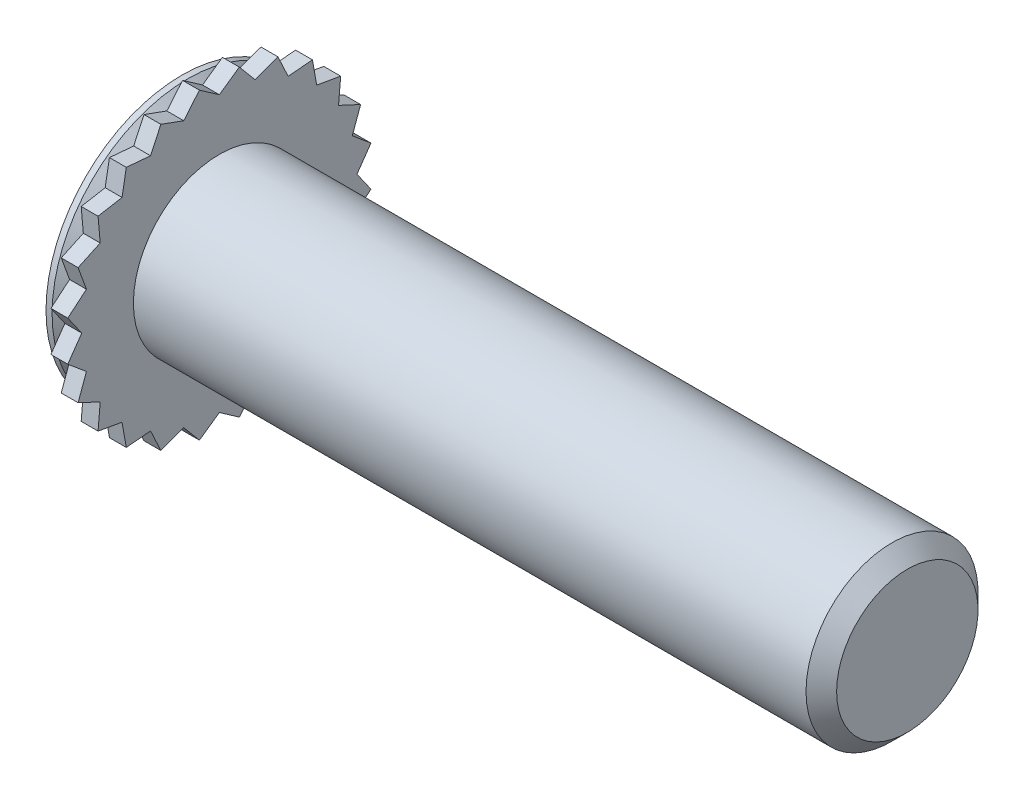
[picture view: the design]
ISO-10303-21;
HEADER;
FILE_DESCRIPTION(('STEP AP214'),'2;1');
FILE_NAME('part.step','',(''),(''),'','','');
FILE_SCHEMA(('AUTOMOTIVE_DESIGN { 1 0 10303 214 1 1 1 1 }'));
ENDSEC;
DATA;
#1=APPLICATION_CONTEXT('core data for automotive mechanical design processes');
#2=APPLICATION_PROTOCOL_DEFINITION('international standard','automotive_design',2000,#1);
#3=PRODUCT_CONTEXT('',#1,'mechanical');
#4=PRODUCT('Part','Part','',(#3));
#5=PRODUCT_RELATED_PRODUCT_CATEGORY('part','',(#4));
#6=PRODUCT_DEFINITION_FORMATION('','',#4);
#7=PRODUCT_DEFINITION_CONTEXT('part definition',#1,'design');
#8=PRODUCT_DEFINITION('design','',#6,#7);
#9=PRODUCT_DEFINITION_SHAPE('','',#8);
#10=(LENGTH_UNIT() NAMED_UNIT(*) SI_UNIT(.MILLI.,.METRE.));
#11=(NAMED_UNIT(*) PLANE_ANGLE_UNIT() SI_UNIT($,.RADIAN.));
#12=(NAMED_UNIT(*) SI_UNIT($,.STERADIAN.) SOLID_ANGLE_UNIT());
#13=UNCERTAINTY_MEASURE_WITH_UNIT(LENGTH_MEASURE(1.E-05),#10,'distance_accuracy_value','');
#14=(GEOMETRIC_REPRESENTATION_CONTEXT(3) GLOBAL_UNCERTAINTY_ASSIGNED_CONTEXT((#13)) GLOBAL_UNIT_ASSIGNED_CONTEXT((#10,
#11,#12)) REPRESENTATION_CONTEXT('',''));
#15=CARTESIAN_POINT('',(0.,0.,0.));
#16=DIRECTION('',(0.,0.,1.));
#17=DIRECTION('',(1.,0.,0.));
#18=AXIS2_PLACEMENT_3D('',#15,#16,#17);
#19=CARTESIAN_POINT('',(1.09,4.445,0.));
#20=DIRECTION('',(1.,0.,0.));
#21=DIRECTION('',(0.,0.,-1.));
#22=AXIS2_PLACEMENT_3D('',#19,#20,#21);
#23=PLANE('',#22);
#24=DIRECTION('',(0.,0.93960568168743,0.34225891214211));
#25=VECTOR('',#24,1.);
#26=CARTESIAN_POINT('',(1.09,1.70102785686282,4.10664452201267));
#27=LINE('',#26,#25);
#28=CARTESIAN_POINT('',(1.09,1.03540558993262,3.86418626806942));
#29=VERTEX_POINT('',#28);
#30=CARTESIAN_POINT('',(1.09,1.70102785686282,4.10664452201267));
#31=VERTEX_POINT('',#30);
#32=EDGE_CURVE('E593',#29,#31,#27,.T.);
#33=ORIENTED_EDGE('',*,*,#32,.F.);
#34=DIRECTION('',(0.,0.642592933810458,-0.766207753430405));
#35=VECTOR('',#34,1.);
#36=CARTESIAN_POINT('',(1.09,1.03540558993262,3.86418626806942));
#37=LINE('',#36,#35);
#38=CARTESIAN_POINT('',(1.09,0.580188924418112,4.40697240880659));
#39=VERTEX_POINT('',#38);
#40=EDGE_CURVE('E597',#39,#29,#37,.T.);
#41=ORIENTED_EDGE('',*,*,#40,.F.);
#42=DIRECTION('',(0.,0.819006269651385,0.57378456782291));
#43=VECTOR('',#42,1.);
#44=CARTESIAN_POINT('',(1.09,0.580188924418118,4.40697240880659));
#45=LINE('',#44,#43);
#46=CARTESIAN_POINT('',(1.09,0.,4.0005));
#47=VERTEX_POINT('',#46);
#48=EDGE_CURVE('E365',#47,#39,#45,.T.);
#49=ORIENTED_EDGE('',*,*,#48,.F.);
#50=DIRECTION('',(0.,0.819006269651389,-0.573784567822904));
#51=VECTOR('',#50,1.);
#52=CARTESIAN_POINT('',(1.09,0.,4.0005));
#53=LINE('',#52,#51);
#54=CARTESIAN_POINT('',(1.09,-0.580188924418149,4.40697240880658));
#55=VERTEX_POINT('',#54);
#56=EDGE_CURVE('E648',#55,#47,#53,.T.);
#57=ORIENTED_EDGE('',*,*,#56,.F.);
#58=DIRECTION('',(0.,0.642592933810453,0.76620775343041));
#59=VECTOR('',#58,1.);
#60=CARTESIAN_POINT('',(1.09,-0.580188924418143,4.40697240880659));
#61=LINE('',#60,#59);
#62=CARTESIAN_POINT('',(1.09,-1.03540558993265,3.86418626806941));
#63=VERTEX_POINT('',#62);
#64=EDGE_CURVE('E347',#63,#55,#61,.T.);
#65=ORIENTED_EDGE('',*,*,#64,.F.);
#66=DIRECTION('',(0.,0.939605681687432,-0.342258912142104));
#67=VECTOR('',#66,1.);
#68=CARTESIAN_POINT('',(1.09,-1.03540558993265,3.86418626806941));
#69=LINE('',#68,#67);
#70=CARTESIAN_POINT('',(1.09,-1.70102785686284,4.10664452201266));
#71=VERTEX_POINT('',#70);
#72=EDGE_CURVE('E662',#71,#63,#69,.T.);
#73=ORIENTED_EDGE('',*,*,#72,.F.);
#74=DIRECTION('',(0.,0.422387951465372,0.906415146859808));
#75=VECTOR('',#74,1.);
#76=CARTESIAN_POINT('',(1.09,-1.70102785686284,4.10664452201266));
#77=LINE('',#76,#75);
#78=CARTESIAN_POINT('',(1.09,-2.00025000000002,3.46453462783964));
#79=VERTEX_POINT('',#78);
#80=EDGE_CURVE('E352',#79,#71,#77,.T.);
#81=ORIENTED_EDGE('',*,*,#80,.F.);
#82=DIRECTION('',(0.,0.996172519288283,-0.0874088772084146));
#83=VECTOR('',#82,1.);
#84=CARTESIAN_POINT('',(1.09,-2.00025000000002,3.46453462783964));
#85=LINE('',#84,#83);
#86=CARTESIAN_POINT('',(1.09,-2.70594455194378,3.52645559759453));
#87=VERTEX_POINT('',#86);
#88=EDGE_CURVE('E368',#87,#79,#85,.T.);
#89=ORIENTED_EDGE('',*,*,#88,.F.);
#90=DIRECTION('',(0.,0.173397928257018,0.984851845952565));
#91=VECTOR('',#90,1.);
#92=CARTESIAN_POINT('',(1.09,-2.70594455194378,3.52645559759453));
#93=LINE('',#92,#91);
#94=CARTESIAN_POINT('',(1.09,-2.8287806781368,2.82878067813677));
#95=VERTEX_POINT('',#94);
#96=EDGE_CURVE('E676',#95,#87,#93,.T.);
#97=ORIENTED_EDGE('',*,*,#96,.F.);
#98=DIRECTION('',(0.,0.984851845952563,0.173397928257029));
#99=VECTOR('',#98,1.);
#100=CARTESIAN_POINT('',(1.09,-2.8287806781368,2.82878067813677));
#101=LINE('',#100,#99);
#102=CARTESIAN_POINT('',(1.09,-3.52645559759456,2.70594455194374));
#103=VERTEX_POINT('',#102);
#104=EDGE_CURVE('E678',#103,#95,#101,.T.);
#105=ORIENTED_EDGE('',*,*,#104,.F.);
#106=DIRECTION('',(0.,-0.087408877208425,0.996172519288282));
#107=VECTOR('',#106,1.);
#108=CARTESIAN_POINT('',(1.09,-3.52645559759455,2.70594455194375));
#109=LINE('',#108,#107);
#110=CARTESIAN_POINT('',(1.09,-3.46453462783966,2.00024999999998));
#111=VERTEX_POINT('',#110);
#112=EDGE_CURVE('E379',#111,#103,#109,.T.);
#113=ORIENTED_EDGE('',*,*,#112,.F.);
#114=DIRECTION('',(0.,0.906415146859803,0.422387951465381));
#115=VECTOR('',#114,1.);
#116=CARTESIAN_POINT('',(1.09,-3.46453462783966,2.00024999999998));
#117=LINE('',#116,#115);
#118=CARTESIAN_POINT('',(1.09,-4.10664452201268,1.7010278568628));
#119=VERTEX_POINT('',#118);
#120=EDGE_CURVE('E377',#119,#111,#117,.T.);
#121=ORIENTED_EDGE('',*,*,#120,.F.);
#122=DIRECTION('',(0.,-0.342258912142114,0.939605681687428));
#123=VECTOR('',#122,1.);
#124=CARTESIAN_POINT('',(1.09,-4.10664452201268,1.7010278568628));
#125=LINE('',#124,#123);
#126=CARTESIAN_POINT('',(1.09,-3.86418626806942,1.03540558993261));
#127=VERTEX_POINT('',#126);
#128=EDGE_CURVE('E688',#127,#119,#125,.T.);
#129=ORIENTED_EDGE('',*,*,#128,.F.);
#130=DIRECTION('',(0.,0.766207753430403,0.642592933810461));
#131=VECTOR('',#130,1.);
#132=CARTESIAN_POINT('',(1.09,-3.86418626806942,1.03540558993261));
#133=LINE('',#132,#131);
#134=CARTESIAN_POINT('',(1.09,-4.40697240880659,0.580188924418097));
#135=VERTEX_POINT('',#134);
#136=EDGE_CURVE('E692',#135,#127,#133,.T.);
#137=ORIENTED_EDGE('',*,*,#136,.F.);
#138=DIRECTION('',(0.,-0.573784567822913,0.819006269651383));
#139=VECTOR('',#138,1.);
#140=CARTESIAN_POINT('',(1.09,-4.40697240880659,0.580188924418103));
#141=LINE('',#140,#139);
#142=CARTESIAN_POINT('',(1.09,-4.0005,0.));
#143=VERTEX_POINT('',#142);
#144=EDGE_CURVE('E396',#143,#135,#141,.T.);
#145=ORIENTED_EDGE('',*,*,#144,.F.);
#146=DIRECTION('',(0.,0.573784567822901,0.819006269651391));
#147=VECTOR('',#146,1.);
#148=CARTESIAN_POINT('',(1.09,-4.0005,0.));
#149=LINE('',#148,#147);
#150=CARTESIAN_POINT('',(1.09,-4.40697240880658,-0.580188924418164));
#151=VERTEX_POINT('',#150);
#152=EDGE_CURVE('E394',#151,#143,#149,.T.);
#153=ORIENTED_EDGE('',*,*,#152,.F.);
#154=DIRECTION('',(0.,-0.766207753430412,0.64259293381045));
#155=VECTOR('',#154,1.);
#156=CARTESIAN_POINT('',(1.09,-4.40697240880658,-0.580188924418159));
#157=LINE('',#156,#155);
#158=CARTESIAN_POINT('',(1.09,-3.86418626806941,-1.03540558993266));
#159=VERTEX_POINT('',#158);
#160=EDGE_CURVE('E703',#159,#151,#157,.T.);
#161=ORIENTED_EDGE('',*,*,#160,.F.);
#162=DIRECTION('',(0.,0.342258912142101,0.939605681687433));
#163=VECTOR('',#162,1.);
#164=CARTESIAN_POINT('',(1.09,-3.86418626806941,-1.03540558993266));
#165=LINE('',#164,#163);
#166=CARTESIAN_POINT('',(1.09,-4.10664452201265,-1.70102785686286));
#167=VERTEX_POINT('',#166);
#168=EDGE_CURVE('E707',#167,#159,#165,.T.);
#169=ORIENTED_EDGE('',*,*,#168,.F.);
#170=DIRECTION('',(0.,-0.906415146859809,0.422387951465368));
#171=VECTOR('',#170,1.);
#172=CARTESIAN_POINT('',(1.09,-4.10664452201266,-1.70102785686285));
#173=LINE('',#172,#171);
#174=CARTESIAN_POINT('',(1.09,-3.46453462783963,-2.00025000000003));
#175=VERTEX_POINT('',#174);
#176=EDGE_CURVE('E413',#175,#167,#173,.T.);
#177=ORIENTED_EDGE('',*,*,#176,.F.);
#178=DIRECTION('',(0.,0.087408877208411,0.996172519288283));
#179=VECTOR('',#178,1.);
#180=CARTESIAN_POINT('',(1.09,-3.46453462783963,-2.00025000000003));
#181=LINE('',#180,#179);
#182=CARTESIAN_POINT('',(1.09,-3.52645559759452,-2.70594455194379));
#183=VERTEX_POINT('',#182);
#184=EDGE_CURVE('E411',#183,#175,#181,.T.);
#185=ORIENTED_EDGE('',*,*,#184,.F.);
#186=DIRECTION('',(0.,-0.984851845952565,0.173397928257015));
#187=VECTOR('',#186,1.);
#188=CARTESIAN_POINT('',(1.09,-3.52645559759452,-2.70594455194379));
#189=LINE('',#188,#187);
#190=CARTESIAN_POINT('',(1.09,-2.82878067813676,-2.82878067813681));
#191=VERTEX_POINT('',#190);
#192=EDGE_CURVE('E718',#191,#183,#189,.T.);
#193=ORIENTED_EDGE('',*,*,#192,.F.);
#194=DIRECTION('',(0.,-0.173397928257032,0.984851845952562));
#195=VECTOR('',#194,1.);
#196=CARTESIAN_POINT('',(1.09,-2.82878067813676,-2.82878067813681));
#197=LINE('',#196,#195);
#198=CARTESIAN_POINT('',(1.09,-2.70594455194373,-3.52645559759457));
#199=VERTEX_POINT('',#198);
#200=EDGE_CURVE('E722',#199,#191,#197,.T.);
#201=ORIENTED_EDGE('',*,*,#200,.F.);
#202=DIRECTION('',(0.,-0.996172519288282,-0.0874088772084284));
#203=VECTOR('',#202,1.);
#204=CARTESIAN_POINT('',(1.09,-2.70594455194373,-3.52645559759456));
#205=LINE('',#204,#203);
#206=CARTESIAN_POINT('',(1.09,-2.00024999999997,-3.46453462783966));
#207=VERTEX_POINT('',#206);
#208=EDGE_CURVE('E430',#207,#199,#205,.T.);
#209=ORIENTED_EDGE('',*,*,#208,.F.);
#210=DIRECTION('',(0.,-0.422387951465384,0.906415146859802));
#211=VECTOR('',#210,1.);
#212=CARTESIAN_POINT('',(1.09,-2.00024999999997,-3.46453462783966));
#213=LINE('',#212,#211);
#214=CARTESIAN_POINT('',(1.09,-1.70102785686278,-4.10664452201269));
#215=VERTEX_POINT('',#214);
#216=EDGE_CURVE('E428',#215,#207,#213,.T.);
#217=ORIENTED_EDGE('',*,*,#216,.F.);
#218=DIRECTION('',(0.,-0.939605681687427,-0.342258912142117));
#219=VECTOR('',#218,1.);
#220=CARTESIAN_POINT('',(1.09,-1.70102785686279,-4.10664452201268));
#221=LINE('',#220,#219);
#222=CARTESIAN_POINT('',(1.09,-1.0354055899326,-3.86418626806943));
#223=VERTEX_POINT('',#222);
#224=EDGE_CURVE('E733',#223,#215,#221,.T.);
#225=ORIENTED_EDGE('',*,*,#224,.F.);
#226=DIRECTION('',(0.,-0.642592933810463,0.7662077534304));
#227=VECTOR('',#226,1.);
#228=CARTESIAN_POINT('',(1.09,-1.0354055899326,-3.86418626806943));
#229=LINE('',#228,#227);
#230=CARTESIAN_POINT('',(1.09,-0.580188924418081,-4.40697240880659));
#231=VERTEX_POINT('',#230);
#232=EDGE_CURVE('E737',#231,#223,#229,.T.);
#233=ORIENTED_EDGE('',*,*,#232,.F.);
#234=DIRECTION('',(0.,-0.819006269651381,-0.573784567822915));
#235=VECTOR('',#234,1.);
#236=CARTESIAN_POINT('',(1.09,-0.580188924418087,-4.40697240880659));
#237=LINE('',#236,#235);
#238=CARTESIAN_POINT('',(1.09,0.,-4.0005));
#239=VERTEX_POINT('',#238);
#240=EDGE_CURVE('E447',#239,#231,#237,.T.);
#241=ORIENTED_EDGE('',*,*,#240,.F.);
#242=DIRECTION('',(0.,-0.819006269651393,0.573784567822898));
#243=VECTOR('',#242,1.);
#244=CARTESIAN_POINT('',(1.09,0.,-4.0005));
#245=LINE('',#244,#243);
#246=CARTESIAN_POINT('',(1.09,0.58018892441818,-4.40697240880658));
#247=VERTEX_POINT('',#246);
#248=EDGE_CURVE('E445',#247,#239,#245,.T.);
#249=ORIENTED_EDGE('',*,*,#248,.F.);
#250=DIRECTION('',(0.,-0.642592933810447,-0.766207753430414));
#251=VECTOR('',#250,1.);
#252=CARTESIAN_POINT('',(1.09,0.580188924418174,-4.40697240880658));
#253=LINE('',#252,#251);
#254=CARTESIAN_POINT('',(1.09,1.03540558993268,-3.86418626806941));
#255=VERTEX_POINT('',#254);
#256=EDGE_CURVE('E748',#255,#247,#253,.T.);
#257=ORIENTED_EDGE('',*,*,#256,.F.);
#258=DIRECTION('',(0.,-0.939605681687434,0.342258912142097));
#259=VECTOR('',#258,1.);
#260=CARTESIAN_POINT('',(1.09,1.03540558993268,-3.86418626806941));
#261=LINE('',#260,#259);
#262=CARTESIAN_POINT('',(1.09,1.70102785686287,-4.10664452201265));
#263=VERTEX_POINT('',#262);
#264=EDGE_CURVE('E752',#263,#255,#261,.T.);
#265=ORIENTED_EDGE('',*,*,#264,.F.);
#266=DIRECTION('',(0.,-0.422387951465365,-0.906415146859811));
#267=VECTOR('',#266,1.);
#268=CARTESIAN_POINT('',(1.09,1.70102785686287,-4.10664452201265));
#269=LINE('',#268,#267);
#270=CARTESIAN_POINT('',(1.09,2.00025000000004,-3.46453462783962));
#271=VERTEX_POINT('',#270);
#272=EDGE_CURVE('E464',#271,#263,#269,.T.);
#273=ORIENTED_EDGE('',*,*,#272,.F.);
#274=DIRECTION('',(0.,-0.996172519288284,0.0874088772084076));
#275=VECTOR('',#274,1.);
#276=CARTESIAN_POINT('',(1.09,2.00025000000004,-3.46453462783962));
#277=LINE('',#276,#275);
#278=CARTESIAN_POINT('',(1.09,2.70594455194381,-3.52645559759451));
#279=VERTEX_POINT('',#278);
#280=EDGE_CURVE('E462',#279,#271,#277,.T.);
#281=ORIENTED_EDGE('',*,*,#280,.F.);
#282=DIRECTION('',(0.,-0.173397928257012,-0.984851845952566));
#283=VECTOR('',#282,1.);
#284=CARTESIAN_POINT('',(1.09,2.7059445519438,-3.52645559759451));
#285=LINE('',#284,#283);
#286=CARTESIAN_POINT('',(1.09,2.82878067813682,-2.82878067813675));
#287=VERTEX_POINT('',#286);
#288=EDGE_CURVE('E763',#287,#279,#285,.T.);
#289=ORIENTED_EDGE('',*,*,#288,.F.);
#290=DIRECTION('',(0.,-0.984851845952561,-0.173397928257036));
#291=VECTOR('',#290,1.);
#292=CARTESIAN_POINT('',(1.09,2.82878067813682,-2.82878067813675));
#293=LINE('',#292,#291);
#294=CARTESIAN_POINT('',(1.09,3.52645559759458,-2.70594455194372));
#295=VERTEX_POINT('',#294);
#296=EDGE_CURVE('E767',#295,#287,#293,.T.);
#297=ORIENTED_EDGE('',*,*,#296,.F.);
#298=DIRECTION('',(0.,0.0874088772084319,-0.996172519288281));
#299=VECTOR('',#298,1.);
#300=CARTESIAN_POINT('',(1.09,3.52645559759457,-2.70594455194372));
#301=LINE('',#300,#299);
#302=CARTESIAN_POINT('',(1.09,3.46453462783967,-2.00024999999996));
#303=VERTEX_POINT('',#302);
#304=EDGE_CURVE('E481',#303,#295,#301,.T.);
#305=ORIENTED_EDGE('',*,*,#304,.F.);
#306=DIRECTION('',(0.,-0.906415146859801,-0.422387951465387));
#307=VECTOR('',#306,1.);
#308=CARTESIAN_POINT('',(1.09,3.46453462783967,-2.00024999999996));
#309=LINE('',#308,#307);
#310=CARTESIAN_POINT('',(1.09,4.10664452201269,-1.70102785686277));
#311=VERTEX_POINT('',#310);
#312=EDGE_CURVE('E479',#311,#303,#309,.T.);
#313=ORIENTED_EDGE('',*,*,#312,.F.);
#314=DIRECTION('',(0.,0.34225891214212,-0.939605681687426));
#315=VECTOR('',#314,1.);
#316=CARTESIAN_POINT('',(1.09,4.10664452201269,-1.70102785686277));
#317=LINE('',#316,#315);
#318=CARTESIAN_POINT('',(1.09,3.86418626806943,-1.03540558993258));
#319=VERTEX_POINT('',#318);
#320=EDGE_CURVE('E778',#319,#311,#317,.T.);
#321=ORIENTED_EDGE('',*,*,#320,.F.);
#322=DIRECTION('',(0.,-0.766207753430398,-0.642592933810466));
#323=VECTOR('',#322,1.);
#324=CARTESIAN_POINT('',(1.09,3.86418626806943,-1.03540558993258));
#325=LINE('',#324,#323);
#326=CARTESIAN_POINT('',(1.09,4.40697240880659,-0.580188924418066));
#327=VERTEX_POINT('',#326);
#328=EDGE_CURVE('E781',#327,#319,#325,.T.);
#329=ORIENTED_EDGE('',*,*,#328,.F.);
#330=DIRECTION('',(0.,0.573784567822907,-0.819006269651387));
#331=VECTOR('',#330,1.);
#332=CARTESIAN_POINT('',(1.09,4.40697240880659,-0.580188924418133));
#333=LINE('',#332,#331);
#334=CARTESIAN_POINT('',(1.09,4.0005,0.));
#335=VERTEX_POINT('',#334);
#336=EDGE_CURVE('E528',#335,#327,#333,.T.);
#337=ORIENTED_EDGE('',*,*,#336,.F.);
#338=DIRECTION('',(0.,-0.573784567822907,-0.819006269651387));
#339=VECTOR('',#338,1.);
#340=CARTESIAN_POINT('',(1.09,4.0005,0.));
#341=LINE('',#340,#339);
#342=CARTESIAN_POINT('',(1.09,4.40697240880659,0.580188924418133));
#343=VERTEX_POINT('',#342);
#344=EDGE_CURVE('E521',#343,#335,#341,.T.);
#345=ORIENTED_EDGE('',*,*,#344,.F.);
#346=DIRECTION('',(0.,0.766207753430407,-0.642592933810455));
#347=VECTOR('',#346,1.);
#348=CARTESIAN_POINT('',(1.09,4.40697240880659,0.580188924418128));
#349=LINE('',#348,#347);
#350=CARTESIAN_POINT('',(1.09,3.86418626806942,1.03540558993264));
#351=VERTEX_POINT('',#350);
#352=EDGE_CURVE('E512',#351,#343,#349,.T.);
#353=ORIENTED_EDGE('',*,*,#352,.F.);
#354=DIRECTION('',(0.,-0.342258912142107,-0.939605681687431));
#355=VECTOR('',#354,1.);
#356=CARTESIAN_POINT('',(1.09,3.86418626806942,1.03540558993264));
#357=LINE('',#356,#355);
#358=CARTESIAN_POINT('',(1.09,4.10664452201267,1.70102785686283));
#359=VERTEX_POINT('',#358);
#360=EDGE_CURVE('E501',#359,#351,#357,.T.);
#361=ORIENTED_EDGE('',*,*,#360,.F.);
#362=DIRECTION('',(0.,0.906415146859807,-0.422387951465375));
#363=VECTOR('',#362,1.);
#364=CARTESIAN_POINT('',(1.09,4.10664452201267,1.70102785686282));
#365=LINE('',#364,#363);
#366=CARTESIAN_POINT('',(1.09,3.46453462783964,2.00025));
#367=VERTEX_POINT('',#366);
#368=EDGE_CURVE('E635',#367,#359,#365,.T.);
#369=ORIENTED_EDGE('',*,*,#368,.F.);
#370=DIRECTION('',(0.,-0.087408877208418,-0.996172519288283));
#371=VECTOR('',#370,1.);
#372=CARTESIAN_POINT('',(1.09,3.46453462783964,2.00025));
#373=LINE('',#372,#371);
#374=CARTESIAN_POINT('',(1.09,3.52645559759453,2.70594455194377));
#375=VERTEX_POINT('',#374);
#376=EDGE_CURVE('E633',#375,#367,#373,.T.);
#377=ORIENTED_EDGE('',*,*,#376,.F.);
#378=DIRECTION('',(0.,0.984851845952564,-0.173397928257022));
#379=VECTOR('',#378,1.);
#380=CARTESIAN_POINT('',(1.09,3.52645559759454,2.70594455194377));
#381=LINE('',#380,#379);
#382=CARTESIAN_POINT('',(1.09,2.82878067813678,2.82878067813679));
#383=VERTEX_POINT('',#382);
#384=EDGE_CURVE('E617',#383,#375,#381,.T.);
#385=ORIENTED_EDGE('',*,*,#384,.F.);
#386=DIRECTION('',(0.,0.173397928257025,-0.984851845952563));
#387=VECTOR('',#386,1.);
#388=CARTESIAN_POINT('',(1.09,2.82878067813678,2.82878067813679));
#389=LINE('',#388,#387);
#390=CARTESIAN_POINT('',(1.09,2.70594455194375,3.52645559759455));
#391=VERTEX_POINT('',#390);
#392=EDGE_CURVE('E610',#391,#383,#389,.T.);
#393=ORIENTED_EDGE('',*,*,#392,.F.);
#394=DIRECTION('',(0.,0.996172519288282,0.0874088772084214));
#395=VECTOR('',#394,1.);
#396=CARTESIAN_POINT('',(1.09,2.70594455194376,3.52645559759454));
#397=LINE('',#396,#395);
#398=CARTESIAN_POINT('',(1.09,2.00024999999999,3.46453462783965));
#399=VERTEX_POINT('',#398);
#400=EDGE_CURVE('E498',#399,#391,#397,.T.);
#401=ORIENTED_EDGE('',*,*,#400,.F.);
#402=DIRECTION('',(0.,0.422387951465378,-0.906415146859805));
#403=VECTOR('',#402,1.);
#404=CARTESIAN_POINT('',(1.09,2.00024999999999,3.46453462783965));
#405=LINE('',#404,#403);
#406=EDGE_CURVE('E496',#31,#399,#405,.T.);
#407=ORIENTED_EDGE('',*,*,#406,.F.);
#408=EDGE_LOOP('',(#33,#41,#49,#57,#65,#73,#81,#89,#97,#105,#113,#121,#129,#137,#145,#153,#161,
#169,#177,#185,#193,#201,#209,#217,#225,#233,#241,#249,#257,#265,#273,#281,#289,#297,#305,#313,
#321,#329,#337,#345,#353,#361,#369,#377,#385,#393,#401,#407));
#409=FACE_BOUND('',#408,.T.);
#410=CARTESIAN_POINT('',(1.09,0.,0.));
#411=DIRECTION('',(-1.,0.,0.));
#412=DIRECTION('',(0.,0.,1.));
#413=AXIS2_PLACEMENT_3D('',#410,#411,#412);
#414=CIRCLE('',#413,2.5);
#415=CARTESIAN_POINT('',(1.09,0.,2.5));
#416=VERTEX_POINT('',#415);
#417=EDGE_CURVE('E11',#416,#416,#414,.T.);
#418=ORIENTED_EDGE('',*,*,#417,.T.);
#419=EDGE_LOOP('',(#418));
#420=FACE_BOUND('',#419,.T.);
#421=ADVANCED_FACE('F32',(#409,#420),#23,.T.);
#422=CARTESIAN_POINT('',(0.,0.,0.));
#423=DIRECTION('',(-1.,0.,0.));
#424=DIRECTION('',(0.,0.,1.));
#425=AXIS2_PLACEMENT_3D('',#422,#423,#424);
#426=CYLINDRICAL_SURFACE('',#425,2.5);
#427=CARTESIAN_POINT('',(20.6449999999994,0.,0.));
#428=DIRECTION('',(-1.,0.,0.));
#429=DIRECTION('',(0.,0.,1.));
#430=AXIS2_PLACEMENT_3D('',#427,#428,#429);
#431=CIRCLE('',#430,2.5);
#432=CARTESIAN_POINT('',(20.6449999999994,0.,2.5));
#433=VERTEX_POINT('',#432);
#434=EDGE_CURVE('E39',#433,#433,#431,.T.);
#435=ORIENTED_EDGE('',*,*,#434,.T.);
#436=EDGE_LOOP('',(#435));
#437=FACE_BOUND('',#436,.T.);
#438=ORIENTED_EDGE('',*,*,#417,.F.);
#439=EDGE_LOOP('',(#438));
#440=FACE_BOUND('',#439,.T.);
#441=ADVANCED_FACE('F565',(#437,#440),#426,.T.);
#442=CARTESIAN_POINT('',(21.09,0.,0.));
#443=DIRECTION('',(-1.,0.,0.));
#444=DIRECTION('',(0.,0.,1.));
#445=AXIS2_PLACEMENT_3D('',#442,#443,#444);
#446=CONICAL_SURFACE('',#445,2.055,0.785398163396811);
#447=ORIENTED_EDGE('',*,*,#434,.F.);
#448=EDGE_LOOP('',(#447));
#449=FACE_BOUND('',#448,.T.);
#450=CARTESIAN_POINT('',(21.09,0.,0.));
#451=DIRECTION('',(-1.,0.,0.));
#452=DIRECTION('',(0.,0.,1.));
#453=AXIS2_PLACEMENT_3D('',#450,#451,#452);
#454=CIRCLE('',#453,2.055);
#455=CARTESIAN_POINT('',(21.09,0.,2.055));
#456=VERTEX_POINT('',#455);
#457=EDGE_CURVE('E560',#456,#456,#454,.T.);
#458=ORIENTED_EDGE('',*,*,#457,.T.);
#459=EDGE_LOOP('',(#458));
#460=FACE_BOUND('',#459,.T.);
#461=ADVANCED_FACE('F568',(#449,#460),#446,.T.);
#462=CARTESIAN_POINT('',(21.09,2.055,0.));
#463=DIRECTION('',(1.,0.,0.));
#464=DIRECTION('',(0.,0.,-1.));
#465=AXIS2_PLACEMENT_3D('',#462,#463,#464);
#466=PLANE('',#465);
#467=ORIENTED_EDGE('',*,*,#457,.F.);
#468=EDGE_LOOP('',(#467));
#469=FACE_BOUND('',#468,.T.);
#470=ADVANCED_FACE('F571',(#469),#466,.T.);
#471=CARTESIAN_POINT('',(0.545,1.6775,0.));
#472=DIRECTION('',(1.,0.,0.));
#473=DIRECTION('',(0.,0.,-1.));
#474=AXIS2_PLACEMENT_3D('',#471,#472,#473);
#475=PLANE('',#474);
#476=CARTESIAN_POINT('',(0.545,0.,0.));
#477=DIRECTION('',(-1.,0.,0.));
#478=DIRECTION('',(0.,0.,1.));
#479=AXIS2_PLACEMENT_3D('',#476,#477,#478);
#480=CIRCLE('',#479,1.6775);
#481=CARTESIAN_POINT('',(0.545,0.,1.6775));
#482=VERTEX_POINT('',#481);
#483=EDGE_CURVE('E557',#482,#482,#480,.T.);
#484=ORIENTED_EDGE('',*,*,#483,.T.);
#485=EDGE_LOOP('',(#484));
#486=FACE_BOUND('',#485,.T.);
#487=ADVANCED_FACE('F576',(#486),#475,.F.);
#488=CARTESIAN_POINT('',(0.,0.,0.));
#489=DIRECTION('',(-1.,0.,0.));
#490=DIRECTION('',(0.,0.,1.));
#491=AXIS2_PLACEMENT_3D('',#488,#489,#490);
#492=CONICAL_SURFACE('',#491,2.2225,0.78539816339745);
#493=ORIENTED_EDGE('',*,*,#483,.F.);
#494=EDGE_LOOP('',(#493));
#495=FACE_BOUND('',#494,.T.);
#496=CARTESIAN_POINT('',(0.,0.,0.));
#497=DIRECTION('',(-1.,0.,0.));
#498=DIRECTION('',(0.,0.,1.));
#499=AXIS2_PLACEMENT_3D('',#496,#497,#498);
#500=CIRCLE('',#499,2.2225);
#501=CARTESIAN_POINT('',(0.,0.,2.2225));
#502=VERTEX_POINT('',#501);
#503=EDGE_CURVE('E554',#502,#502,#500,.T.);
#504=ORIENTED_EDGE('',*,*,#503,.T.);
#505=EDGE_LOOP('',(#504));
#506=FACE_BOUND('',#505,.T.);
#507=ADVANCED_FACE('F581',(#495,#506),#492,.F.);
#508=CARTESIAN_POINT('',(0.,2.2225,0.));
#509=DIRECTION('',(-1.,0.,0.));
#510=DIRECTION('',(0.,0.,1.));
#511=AXIS2_PLACEMENT_3D('',#508,#509,#510);
#512=PLANE('',#511);
#513=CARTESIAN_POINT('',(0.,0.,0.));
#514=DIRECTION('',(-1.,0.,0.));
#515=DIRECTION('',(0.,0.,1.));
#516=AXIS2_PLACEMENT_3D('',#513,#514,#515);
#517=CIRCLE('',#516,3.95);
#518=CARTESIAN_POINT('',(0.,0.,3.95));
#519=VERTEX_POINT('',#518);
#520=EDGE_CURVE('E551',#519,#519,#517,.T.);
#521=ORIENTED_EDGE('',*,*,#520,.T.);
#522=EDGE_LOOP('',(#521));
#523=FACE_BOUND('',#522,.T.);
#524=ORIENTED_EDGE('',*,*,#503,.F.);
#525=EDGE_LOOP('',(#524));
#526=FACE_BOUND('',#525,.T.);
#527=ADVANCED_FACE('F1062',(#523,#526),#512,.T.);
#528=CARTESIAN_POINT('',(0.,0.,0.));
#529=DIRECTION('',(-1.,0.,0.));
#530=DIRECTION('',(0.,0.,1.));
#531=AXIS2_PLACEMENT_3D('',#528,#529,#530);
#532=CYLINDRICAL_SURFACE('',#531,3.95);
#533=ORIENTED_EDGE('',*,*,#520,.F.);
#534=EDGE_LOOP('',(#533));
#535=FACE_BOUND('',#534,.T.);
#536=CARTESIAN_POINT('',(0.1778,0.,0.));
#537=DIRECTION('',(-1.,0.,0.));
#538=DIRECTION('',(0.,0.,1.));
#539=AXIS2_PLACEMENT_3D('',#536,#537,#538);
#540=CIRCLE('',#539,3.95);
#541=CARTESIAN_POINT('',(0.1778,0.,3.95));
#542=VERTEX_POINT('',#541);
#543=EDGE_CURVE('E548',#542,#542,#540,.T.);
#544=ORIENTED_EDGE('',*,*,#543,.T.);
#545=EDGE_LOOP('',(#544));
#546=FACE_BOUND('',#545,.T.);
#547=ADVANCED_FACE('F1058',(#535,#546),#532,.T.);
#548=CARTESIAN_POINT('',(0.4905,0.,0.));
#549=DIRECTION('',(-1.,0.,0.));
#550=DIRECTION('',(0.,0.,1.));
#551=AXIS2_PLACEMENT_3D('',#548,#549,#550);
#552=CONICAL_SURFACE('',#551,3.6373,0.785398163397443);
#553=ORIENTED_EDGE('',*,*,#543,.F.);
#554=EDGE_LOOP('',(#553));
#555=FACE_BOUND('',#554,.T.);
#556=CARTESIAN_POINT('',(0.4905,0.,0.));
#557=DIRECTION('',(-1.,0.,0.));
#558=DIRECTION('',(0.,0.,1.));
#559=AXIS2_PLACEMENT_3D('',#556,#557,#558);
#560=CIRCLE('',#559,3.6373);
#561=CARTESIAN_POINT('',(0.4905,0.,3.6373));
#562=VERTEX_POINT('',#561);
#563=EDGE_CURVE('E545',#562,#562,#560,.T.);
#564=ORIENTED_EDGE('',*,*,#563,.T.);
#565=EDGE_LOOP('',(#564));
#566=FACE_BOUND('',#565,.T.);
#567=ADVANCED_FACE('F1054',(#555,#566),#552,.T.);
#568=CARTESIAN_POINT('',(0.,0.,0.));
#569=DIRECTION('',(-1.,0.,0.));
#570=DIRECTION('',(0.,0.,1.));
#571=AXIS2_PLACEMENT_3D('',#568,#569,#570);
#572=CYLINDRICAL_SURFACE('',#571,3.6373);
#573=ORIENTED_EDGE('',*,*,#563,.F.);
#574=EDGE_LOOP('',(#573));
#575=FACE_BOUND('',#574,.T.);
#576=CARTESIAN_POINT('',(0.5995,0.,0.));
#577=DIRECTION('',(-1.,0.,0.));
#578=DIRECTION('',(0.,0.,1.));
#579=AXIS2_PLACEMENT_3D('',#576,#577,#578);
#580=CIRCLE('',#579,3.6373);
#581=CARTESIAN_POINT('',(0.5995,0.,3.6373));
#582=VERTEX_POINT('',#581);
#583=EDGE_CURVE('E538',#582,#582,#580,.T.);
#584=ORIENTED_EDGE('',*,*,#583,.T.);
#585=EDGE_LOOP('',(#584));
#586=FACE_BOUND('',#585,.T.);
#587=ADVANCED_FACE('F1050',(#575,#586),#572,.T.);
#588=CARTESIAN_POINT('',(0.5995,4.445,0.));
#589=DIRECTION('',(1.,0.,0.));
#590=DIRECTION('',(0.,0.,-1.));
#591=AXIS2_PLACEMENT_3D('',#588,#589,#590);
#592=PLANE('',#591);
#593=ORIENTED_EDGE('',*,*,#583,.F.);
#594=EDGE_LOOP('',(#593));
#595=FACE_BOUND('',#594,.T.);
#596=DIRECTION('',(0.,0.642592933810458,-0.766207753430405));
#597=VECTOR('',#596,1.);
#598=CARTESIAN_POINT('',(0.5995,1.03540558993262,3.86418626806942));
#599=LINE('',#598,#597);
#600=CARTESIAN_POINT('',(0.5995,0.580188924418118,4.40697240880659));
#601=VERTEX_POINT('',#600);
#602=CARTESIAN_POINT('',(0.5995,1.03540558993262,3.86418626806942));
#603=VERTEX_POINT('',#602);
#604=EDGE_CURVE('E601',#601,#603,#599,.T.);
#605=ORIENTED_EDGE('',*,*,#604,.T.);
#606=DIRECTION('',(0.,0.93960568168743,0.34225891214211));
#607=VECTOR('',#606,1.);
#608=CARTESIAN_POINT('',(0.5995,1.70102785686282,4.10664452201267));
#609=LINE('',#608,#607);
#610=CARTESIAN_POINT('',(0.5995,1.70102785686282,4.10664452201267));
#611=VERTEX_POINT('',#610);
#612=EDGE_CURVE('E603',#603,#611,#609,.T.);
#613=ORIENTED_EDGE('',*,*,#612,.T.);
#614=DIRECTION('',(0.,0.422387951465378,-0.906415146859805));
#615=VECTOR('',#614,1.);
#616=CARTESIAN_POINT('',(0.5995,2.00024999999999,3.46453462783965));
#617=LINE('',#616,#615);
#618=CARTESIAN_POINT('',(0.5995,2.00024999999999,3.46453462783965));
#619=VERTEX_POINT('',#618);
#620=EDGE_CURVE('E497',#611,#619,#617,.T.);
#621=ORIENTED_EDGE('',*,*,#620,.T.);
#622=DIRECTION('',(0.,0.996172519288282,0.0874088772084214));
#623=VECTOR('',#622,1.);
#624=CARTESIAN_POINT('',(0.5995,2.70594455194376,3.52645559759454));
#625=LINE('',#624,#623);
#626=CARTESIAN_POINT('',(0.5995,2.70594455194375,3.52645559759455));
#627=VERTEX_POINT('',#626);
#628=EDGE_CURVE('E493',#619,#627,#625,.T.);
#629=ORIENTED_EDGE('',*,*,#628,.T.);
#630=DIRECTION('',(0.,0.173397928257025,-0.984851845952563));
#631=VECTOR('',#630,1.);
#632=CARTESIAN_POINT('',(0.5995,2.82878067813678,2.82878067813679));
#633=LINE('',#632,#631);
#634=CARTESIAN_POINT('',(0.5995,2.82878067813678,2.82878067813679));
#635=VERTEX_POINT('',#634);
#636=EDGE_CURVE('E613',#627,#635,#633,.T.);
#637=ORIENTED_EDGE('',*,*,#636,.T.);
#638=DIRECTION('',(0.,0.984851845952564,-0.173397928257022));
#639=VECTOR('',#638,1.);
#640=CARTESIAN_POINT('',(0.5995,3.52645559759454,2.70594455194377));
#641=LINE('',#640,#639);
#642=CARTESIAN_POINT('',(0.5995,3.52645559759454,2.70594455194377));
#643=VERTEX_POINT('',#642);
#644=EDGE_CURVE('E616',#635,#643,#641,.T.);
#645=ORIENTED_EDGE('',*,*,#644,.T.);
#646=DIRECTION('',(0.,-0.087408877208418,-0.996172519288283));
#647=VECTOR('',#646,1.);
#648=CARTESIAN_POINT('',(0.5995,3.46453462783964,2.00025));
#649=LINE('',#648,#647);
#650=CARTESIAN_POINT('',(0.5995,3.46453462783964,2.00025));
#651=VERTEX_POINT('',#650);
#652=EDGE_CURVE('E634',#643,#651,#649,.T.);
#653=ORIENTED_EDGE('',*,*,#652,.T.);
#654=DIRECTION('',(0.,0.906415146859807,-0.422387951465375));
#655=VECTOR('',#654,1.);
#656=CARTESIAN_POINT('',(0.5995,4.10664452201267,1.70102785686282));
#657=LINE('',#656,#655);
#658=CARTESIAN_POINT('',(0.5995,4.10664452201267,1.70102785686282));
#659=VERTEX_POINT('',#658);
#660=EDGE_CURVE('E630',#651,#659,#657,.T.);
#661=ORIENTED_EDGE('',*,*,#660,.T.);
#662=DIRECTION('',(0.,-0.342258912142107,-0.939605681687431));
#663=VECTOR('',#662,1.);
#664=CARTESIAN_POINT('',(0.5995,3.86418626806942,1.03540558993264));
#665=LINE('',#664,#663);
#666=CARTESIAN_POINT('',(0.5995,3.86418626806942,1.03540558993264));
#667=VERTEX_POINT('',#666);
#668=EDGE_CURVE('E508',#659,#667,#665,.T.);
#669=ORIENTED_EDGE('',*,*,#668,.T.);
#670=DIRECTION('',(0.,0.766207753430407,-0.642592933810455));
#671=VECTOR('',#670,1.);
#672=CARTESIAN_POINT('',(0.5995,4.40697240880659,0.580188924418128));
#673=LINE('',#672,#671);
#674=CARTESIAN_POINT('',(0.5995,4.40697240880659,0.580188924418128));
#675=VERTEX_POINT('',#674);
#676=EDGE_CURVE('E511',#667,#675,#673,.T.);
#677=ORIENTED_EDGE('',*,*,#676,.T.);
#678=DIRECTION('',(0.,-0.573784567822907,-0.819006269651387));
#679=VECTOR('',#678,1.);
#680=CARTESIAN_POINT('',(0.5995,4.0005,0.));
#681=LINE('',#680,#679);
#682=CARTESIAN_POINT('',(0.5995,4.0005,0.));
#683=VERTEX_POINT('',#682);
#684=EDGE_CURVE('E524',#675,#683,#681,.T.);
#685=ORIENTED_EDGE('',*,*,#684,.T.);
#686=DIRECTION('',(0.,0.573784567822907,-0.819006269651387));
#687=VECTOR('',#686,1.);
#688=CARTESIAN_POINT('',(0.5995,4.40697240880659,-0.580188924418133));
#689=LINE('',#688,#687);
#690=CARTESIAN_POINT('',(0.5995,4.40697240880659,-0.580188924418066));
#691=VERTEX_POINT('',#690);
#692=EDGE_CURVE('E527',#683,#691,#689,.T.);
#693=ORIENTED_EDGE('',*,*,#692,.T.);
#694=DIRECTION('',(0.,-0.766207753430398,-0.642592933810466));
#695=VECTOR('',#694,1.);
#696=CARTESIAN_POINT('',(0.5995,3.86418626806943,-1.03540558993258));
#697=LINE('',#696,#695);
#698=CARTESIAN_POINT('',(0.5995,3.86418626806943,-1.03540558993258));
#699=VERTEX_POINT('',#698);
#700=EDGE_CURVE('E774',#691,#699,#697,.T.);
#701=ORIENTED_EDGE('',*,*,#700,.T.);
#702=DIRECTION('',(0.,0.34225891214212,-0.939605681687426));
#703=VECTOR('',#702,1.);
#704=CARTESIAN_POINT('',(0.5995,4.10664452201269,-1.70102785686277));
#705=LINE('',#704,#703);
#706=CARTESIAN_POINT('',(0.5995,4.10664452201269,-1.70102785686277));
#707=VERTEX_POINT('',#706);
#708=EDGE_CURVE('E777',#699,#707,#705,.T.);
#709=ORIENTED_EDGE('',*,*,#708,.T.);
#710=DIRECTION('',(0.,-0.906415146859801,-0.422387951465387));
#711=VECTOR('',#710,1.);
#712=CARTESIAN_POINT('',(0.5995,3.46453462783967,-2.00024999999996));
#713=LINE('',#712,#711);
#714=CARTESIAN_POINT('',(0.5995,3.46453462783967,-2.00024999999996));
#715=VERTEX_POINT('',#714);
#716=EDGE_CURVE('E480',#707,#715,#713,.T.);
#717=ORIENTED_EDGE('',*,*,#716,.T.);
#718=DIRECTION('',(0.,0.0874088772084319,-0.996172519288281));
#719=VECTOR('',#718,1.);
#720=CARTESIAN_POINT('',(0.5995,3.52645559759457,-2.70594455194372));
#721=LINE('',#720,#719);
#722=CARTESIAN_POINT('',(0.5995,3.52645559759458,-2.70594455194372));
#723=VERTEX_POINT('',#722);
#724=EDGE_CURVE('E476',#715,#723,#721,.T.);
#725=ORIENTED_EDGE('',*,*,#724,.T.);
#726=DIRECTION('',(0.,-0.984851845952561,-0.173397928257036));
#727=VECTOR('',#726,1.);
#728=CARTESIAN_POINT('',(0.5995,2.82878067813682,-2.82878067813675));
#729=LINE('',#728,#727);
#730=CARTESIAN_POINT('',(0.5995,2.82878067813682,-2.82878067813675));
#731=VERTEX_POINT('',#730);
#732=EDGE_CURVE('E759',#723,#731,#729,.T.);
#733=ORIENTED_EDGE('',*,*,#732,.T.);
#734=DIRECTION('',(0.,-0.173397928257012,-0.984851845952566));
#735=VECTOR('',#734,1.);
#736=CARTESIAN_POINT('',(0.5995,2.7059445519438,-3.52645559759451));
#737=LINE('',#736,#735);
#738=CARTESIAN_POINT('',(0.5995,2.7059445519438,-3.52645559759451));
#739=VERTEX_POINT('',#738);
#740=EDGE_CURVE('E762',#731,#739,#737,.T.);
#741=ORIENTED_EDGE('',*,*,#740,.T.);
#742=DIRECTION('',(0.,-0.996172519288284,0.0874088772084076));
#743=VECTOR('',#742,1.);
#744=CARTESIAN_POINT('',(0.5995,2.00025000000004,-3.46453462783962));
#745=LINE('',#744,#743);
#746=CARTESIAN_POINT('',(0.5995,2.00025000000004,-3.46453462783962));
#747=VERTEX_POINT('',#746);
#748=EDGE_CURVE('E463',#739,#747,#745,.T.);
#749=ORIENTED_EDGE('',*,*,#748,.T.);
#750=DIRECTION('',(0.,-0.422387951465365,-0.906415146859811));
#751=VECTOR('',#750,1.);
#752=CARTESIAN_POINT('',(0.5995,1.70102785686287,-4.10664452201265));
#753=LINE('',#752,#751);
#754=CARTESIAN_POINT('',(0.5995,1.70102785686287,-4.10664452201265));
#755=VERTEX_POINT('',#754);
#756=EDGE_CURVE('E459',#747,#755,#753,.T.);
#757=ORIENTED_EDGE('',*,*,#756,.T.);
#758=DIRECTION('',(0.,-0.939605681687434,0.342258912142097));
#759=VECTOR('',#758,1.);
#760=CARTESIAN_POINT('',(0.5995,1.03540558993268,-3.86418626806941));
#761=LINE('',#760,#759);
#762=CARTESIAN_POINT('',(0.5995,1.03540558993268,-3.86418626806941));
#763=VERTEX_POINT('',#762);
#764=EDGE_CURVE('E744',#755,#763,#761,.T.);
#765=ORIENTED_EDGE('',*,*,#764,.T.);
#766=DIRECTION('',(0.,-0.642592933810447,-0.766207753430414));
#767=VECTOR('',#766,1.);
#768=CARTESIAN_POINT('',(0.5995,0.580188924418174,-4.40697240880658));
#769=LINE('',#768,#767);
#770=CARTESIAN_POINT('',(0.5995,0.580188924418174,-4.40697240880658));
#771=VERTEX_POINT('',#770);
#772=EDGE_CURVE('E747',#763,#771,#769,.T.);
#773=ORIENTED_EDGE('',*,*,#772,.T.);
#774=DIRECTION('',(0.,-0.819006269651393,0.573784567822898));
#775=VECTOR('',#774,1.);
#776=CARTESIAN_POINT('',(0.5995,0.,-4.0005));
#777=LINE('',#776,#775);
#778=CARTESIAN_POINT('',(0.5995,0.,-4.0005));
#779=VERTEX_POINT('',#778);
#780=EDGE_CURVE('E446',#771,#779,#777,.T.);
#781=ORIENTED_EDGE('',*,*,#780,.T.);
#782=DIRECTION('',(0.,-0.819006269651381,-0.573784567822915));
#783=VECTOR('',#782,1.);
#784=CARTESIAN_POINT('',(0.5995,-0.580188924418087,-4.40697240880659));
#785=LINE('',#784,#783);
#786=CARTESIAN_POINT('',(0.5995,-0.580188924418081,-4.40697240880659));
#787=VERTEX_POINT('',#786);
#788=EDGE_CURVE('E442',#779,#787,#785,.T.);
#789=ORIENTED_EDGE('',*,*,#788,.T.);
#790=DIRECTION('',(0.,-0.642592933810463,0.7662077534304));
#791=VECTOR('',#790,1.);
#792=CARTESIAN_POINT('',(0.5995,-1.0354055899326,-3.86418626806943));
#793=LINE('',#792,#791);
#794=CARTESIAN_POINT('',(0.5995,-1.0354055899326,-3.86418626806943));
#795=VERTEX_POINT('',#794);
#796=EDGE_CURVE('E729',#787,#795,#793,.T.);
#797=ORIENTED_EDGE('',*,*,#796,.T.);
#798=DIRECTION('',(0.,-0.939605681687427,-0.342258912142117));
#799=VECTOR('',#798,1.);
#800=CARTESIAN_POINT('',(0.5995,-1.70102785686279,-4.10664452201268));
#801=LINE('',#800,#799);
#802=CARTESIAN_POINT('',(0.5995,-1.70102785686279,-4.10664452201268));
#803=VERTEX_POINT('',#802);
#804=EDGE_CURVE('E732',#795,#803,#801,.T.);
#805=ORIENTED_EDGE('',*,*,#804,.T.);
#806=DIRECTION('',(0.,-0.422387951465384,0.906415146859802));
#807=VECTOR('',#806,1.);
#808=CARTESIAN_POINT('',(0.5995,-2.00024999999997,-3.46453462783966));
#809=LINE('',#808,#807);
#810=CARTESIAN_POINT('',(0.5995,-2.00024999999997,-3.46453462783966));
#811=VERTEX_POINT('',#810);
#812=EDGE_CURVE('E429',#803,#811,#809,.T.);
#813=ORIENTED_EDGE('',*,*,#812,.T.);
#814=DIRECTION('',(0.,-0.996172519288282,-0.0874088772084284));
#815=VECTOR('',#814,1.);
#816=CARTESIAN_POINT('',(0.5995,-2.70594455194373,-3.52645559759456));
#817=LINE('',#816,#815);
#818=CARTESIAN_POINT('',(0.5995,-2.70594455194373,-3.52645559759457));
#819=VERTEX_POINT('',#818);
#820=EDGE_CURVE('E425',#811,#819,#817,.T.);
#821=ORIENTED_EDGE('',*,*,#820,.T.);
#822=DIRECTION('',(0.,-0.173397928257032,0.984851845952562));
#823=VECTOR('',#822,1.);
#824=CARTESIAN_POINT('',(0.5995,-2.82878067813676,-2.82878067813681));
#825=LINE('',#824,#823);
#826=CARTESIAN_POINT('',(0.5995,-2.82878067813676,-2.82878067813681));
#827=VERTEX_POINT('',#826);
#828=EDGE_CURVE('E714',#819,#827,#825,.T.);
#829=ORIENTED_EDGE('',*,*,#828,.T.);
#830=DIRECTION('',(0.,-0.984851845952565,0.173397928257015));
#831=VECTOR('',#830,1.);
#832=CARTESIAN_POINT('',(0.5995,-3.52645559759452,-2.70594455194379));
#833=LINE('',#832,#831);
#834=CARTESIAN_POINT('',(0.5995,-3.52645559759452,-2.70594455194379));
#835=VERTEX_POINT('',#834);
#836=EDGE_CURVE('E717',#827,#835,#833,.T.);
#837=ORIENTED_EDGE('',*,*,#836,.T.);
#838=DIRECTION('',(0.,0.087408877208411,0.996172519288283));
#839=VECTOR('',#838,1.);
#840=CARTESIAN_POINT('',(0.5995,-3.46453462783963,-2.00025000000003));
#841=LINE('',#840,#839);
#842=CARTESIAN_POINT('',(0.5995,-3.46453462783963,-2.00025000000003));
#843=VERTEX_POINT('',#842);
#844=EDGE_CURVE('E412',#835,#843,#841,.T.);
#845=ORIENTED_EDGE('',*,*,#844,.T.);
#846=DIRECTION('',(0.,-0.906415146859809,0.422387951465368));
#847=VECTOR('',#846,1.);
#848=CARTESIAN_POINT('',(0.5995,-4.10664452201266,-1.70102785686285));
#849=LINE('',#848,#847);
#850=CARTESIAN_POINT('',(0.5995,-4.10664452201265,-1.70102785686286));
#851=VERTEX_POINT('',#850);
#852=EDGE_CURVE('E408',#843,#851,#849,.T.);
#853=ORIENTED_EDGE('',*,*,#852,.T.);
#854=DIRECTION('',(0.,0.342258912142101,0.939605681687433));
#855=VECTOR('',#854,1.);
#856=CARTESIAN_POINT('',(0.5995,-3.86418626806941,-1.03540558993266));
#857=LINE('',#856,#855);
#858=CARTESIAN_POINT('',(0.5995,-3.86418626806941,-1.03540558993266));
#859=VERTEX_POINT('',#858);
#860=EDGE_CURVE('E699',#851,#859,#857,.T.);
#861=ORIENTED_EDGE('',*,*,#860,.T.);
#862=DIRECTION('',(0.,-0.766207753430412,0.64259293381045));
#863=VECTOR('',#862,1.);
#864=CARTESIAN_POINT('',(0.5995,-4.40697240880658,-0.580188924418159));
#865=LINE('',#864,#863);
#866=CARTESIAN_POINT('',(0.5995,-4.40697240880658,-0.580188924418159));
#867=VERTEX_POINT('',#866);
#868=EDGE_CURVE('E702',#859,#867,#865,.T.);
#869=ORIENTED_EDGE('',*,*,#868,.T.);
#870=DIRECTION('',(0.,0.573784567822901,0.819006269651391));
#871=VECTOR('',#870,1.);
#872=CARTESIAN_POINT('',(0.5995,-4.0005,0.));
#873=LINE('',#872,#871);
#874=CARTESIAN_POINT('',(0.5995,-4.0005,0.));
#875=VERTEX_POINT('',#874);
#876=EDGE_CURVE('E395',#867,#875,#873,.T.);
#877=ORIENTED_EDGE('',*,*,#876,.T.);
#878=DIRECTION('',(0.,-0.573784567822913,0.819006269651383));
#879=VECTOR('',#878,1.);
#880=CARTESIAN_POINT('',(0.5995,-4.40697240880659,0.580188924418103));
#881=LINE('',#880,#879);
#882=CARTESIAN_POINT('',(0.5995,-4.40697240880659,0.580188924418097));
#883=VERTEX_POINT('',#882);
#884=EDGE_CURVE('E391',#875,#883,#881,.T.);
#885=ORIENTED_EDGE('',*,*,#884,.T.);
#886=DIRECTION('',(0.,0.766207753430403,0.642592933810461));
#887=VECTOR('',#886,1.);
#888=CARTESIAN_POINT('',(0.5995,-3.86418626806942,1.03540558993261));
#889=LINE('',#888,#887);
#890=CARTESIAN_POINT('',(0.5995,-3.86418626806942,1.03540558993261));
#891=VERTEX_POINT('',#890);
#892=EDGE_CURVE('E684',#883,#891,#889,.T.);
#893=ORIENTED_EDGE('',*,*,#892,.T.);
#894=DIRECTION('',(0.,-0.342258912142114,0.939605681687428));
#895=VECTOR('',#894,1.);
#896=CARTESIAN_POINT('',(0.5995,-4.10664452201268,1.7010278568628));
#897=LINE('',#896,#895);
#898=CARTESIAN_POINT('',(0.5995,-4.10664452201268,1.7010278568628));
#899=VERTEX_POINT('',#898);
#900=EDGE_CURVE('E687',#891,#899,#897,.T.);
#901=ORIENTED_EDGE('',*,*,#900,.T.);
#902=DIRECTION('',(0.,0.906415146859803,0.422387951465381));
#903=VECTOR('',#902,1.);
#904=CARTESIAN_POINT('',(0.5995,-3.46453462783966,2.00024999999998));
#905=LINE('',#904,#903);
#906=CARTESIAN_POINT('',(0.5995,-3.46453462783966,2.00024999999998));
#907=VERTEX_POINT('',#906);
#908=EDGE_CURVE('E378',#899,#907,#905,.T.);
#909=ORIENTED_EDGE('',*,*,#908,.T.);
#910=DIRECTION('',(0.,-0.087408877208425,0.996172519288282));
#911=VECTOR('',#910,1.);
#912=CARTESIAN_POINT('',(0.5995,-3.52645559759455,2.70594455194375));
#913=LINE('',#912,#911);
#914=CARTESIAN_POINT('',(0.5995,-3.52645559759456,2.70594455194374));
#915=VERTEX_POINT('',#914);
#916=EDGE_CURVE('E374',#907,#915,#913,.T.);
#917=ORIENTED_EDGE('',*,*,#916,.T.);
#918=DIRECTION('',(0.,0.984851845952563,0.173397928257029));
#919=VECTOR('',#918,1.);
#920=CARTESIAN_POINT('',(0.5995,-2.8287806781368,2.82878067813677));
#921=LINE('',#920,#919);
#922=CARTESIAN_POINT('',(0.5995,-2.8287806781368,2.82878067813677));
#923=VERTEX_POINT('',#922);
#924=EDGE_CURVE('E672',#915,#923,#921,.T.);
#925=ORIENTED_EDGE('',*,*,#924,.T.);
#926=DIRECTION('',(0.,0.173397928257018,0.984851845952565));
#927=VECTOR('',#926,1.);
#928=CARTESIAN_POINT('',(0.5995,-2.70594455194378,3.52645559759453));
#929=LINE('',#928,#927);
#930=CARTESIAN_POINT('',(0.5995,-2.70594455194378,3.52645559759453));
#931=VERTEX_POINT('',#930);
#932=EDGE_CURVE('E675',#923,#931,#929,.T.);
#933=ORIENTED_EDGE('',*,*,#932,.T.);
#934=DIRECTION('',(0.,0.996172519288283,-0.0874088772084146));
#935=VECTOR('',#934,1.);
#936=CARTESIAN_POINT('',(0.5995,-2.00025000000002,3.46453462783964));
#937=LINE('',#936,#935);
#938=CARTESIAN_POINT('',(0.5995,-2.00025000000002,3.46453462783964));
#939=VERTEX_POINT('',#938);
#940=EDGE_CURVE('E359',#931,#939,#937,.T.);
#941=ORIENTED_EDGE('',*,*,#940,.T.);
#942=DIRECTION('',(0.,0.422387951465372,0.906415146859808));
#943=VECTOR('',#942,1.);
#944=CARTESIAN_POINT('',(0.5995,-1.70102785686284,4.10664452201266));
#945=LINE('',#944,#943);
#946=CARTESIAN_POINT('',(0.5995,-1.70102785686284,4.10664452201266));
#947=VERTEX_POINT('',#946);
#948=EDGE_CURVE('E54',#939,#947,#945,.T.);
#949=ORIENTED_EDGE('',*,*,#948,.T.);
#950=DIRECTION('',(0.,0.939605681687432,-0.342258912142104));
#951=VECTOR('',#950,1.);
#952=CARTESIAN_POINT('',(0.5995,-1.03540558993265,3.86418626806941));
#953=LINE('',#952,#951);
#954=CARTESIAN_POINT('',(0.5995,-1.03540558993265,3.86418626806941));
#955=VERTEX_POINT('',#954);
#956=EDGE_CURVE('E337',#947,#955,#953,.T.);
#957=ORIENTED_EDGE('',*,*,#956,.T.);
#958=DIRECTION('',(0.,0.642592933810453,0.76620775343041));
#959=VECTOR('',#958,1.);
#960=CARTESIAN_POINT('',(0.5995,-0.580188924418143,4.40697240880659));
#961=LINE('',#960,#959);
#962=CARTESIAN_POINT('',(0.5995,-0.580188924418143,4.40697240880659));
#963=VERTEX_POINT('',#962);
#964=EDGE_CURVE('E346',#955,#963,#961,.T.);
#965=ORIENTED_EDGE('',*,*,#964,.T.);
#966=DIRECTION('',(0.,0.819006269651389,-0.573784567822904));
#967=VECTOR('',#966,1.);
#968=CARTESIAN_POINT('',(0.5995,0.,4.0005));
#969=LINE('',#968,#967);
#970=CARTESIAN_POINT('',(0.5995,0.,4.0005));
#971=VERTEX_POINT('',#970);
#972=EDGE_CURVE('E649',#963,#971,#969,.T.);
#973=ORIENTED_EDGE('',*,*,#972,.T.);
#974=DIRECTION('',(0.,0.819006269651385,0.57378456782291));
#975=VECTOR('',#974,1.);
#976=CARTESIAN_POINT('',(0.5995,0.580188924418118,4.40697240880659));
#977=LINE('',#976,#975);
#978=EDGE_CURVE('E46',#971,#601,#977,.T.);
#979=ORIENTED_EDGE('',*,*,#978,.T.);
#980=EDGE_LOOP('',(#605,#613,#621,#629,#637,#645,#653,#661,#669,#677,#685,#693,#701,#709,#717,
#725,#733,#741,#749,#757,#765,#773,#781,#789,#797,#805,#813,#821,#829,#837,#845,#853,#861,#869,
#877,#885,#893,#901,#909,#917,#925,#933,#941,#949,#957,#965,#973,#979));
#981=FACE_BOUND('',#980,.T.);
#982=ADVANCED_FACE('F356',(#595,#981),#592,.F.);
#983=CARTESIAN_POINT('',(0.5995,4.40697240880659,-0.580188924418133));
#984=DIRECTION('',(0.,-0.819006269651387,-0.573784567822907));
#985=DIRECTION('',(0.,0.573784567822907,-0.819006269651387));
#986=AXIS2_PLACEMENT_3D('',#983,#984,#985);
#987=PLANE('',#986);
#988=ORIENTED_EDGE('',*,*,#336,.T.);
#989=DIRECTION('',(1.,0.,0.));
#990=VECTOR('',#989,1.);
#991=CARTESIAN_POINT('',(0.5995,4.40697240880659,-0.580188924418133));
#992=LINE('',#991,#990);
#993=EDGE_CURVE('E536',#691,#327,#992,.T.);
#994=ORIENTED_EDGE('',*,*,#993,.F.);
#995=ORIENTED_EDGE('',*,*,#692,.F.);
#996=DIRECTION('',(1.,0.,0.));
#997=VECTOR('',#996,1.);
#998=CARTESIAN_POINT('',(0.5995,4.0005,0.));
#999=LINE('',#998,#997);
#1000=EDGE_CURVE('E539',#683,#335,#999,.T.);
#1001=ORIENTED_EDGE('',*,*,#1000,.T.);
#1002=EDGE_LOOP('',(#988,#994,#995,#1001));
#1003=FACE_BOUND('',#1002,.T.);
#1004=ADVANCED_FACE('F824',(#1003),#987,.F.);
#1005=CARTESIAN_POINT('',(0.5995,4.0005,0.));
#1006=DIRECTION('',(0.,-0.819006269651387,0.573784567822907));
#1007=DIRECTION('',(0.,-0.573784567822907,-0.819006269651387));
#1008=AXIS2_PLACEMENT_3D('',#1005,#1006,#1007);
#1009=PLANE('',#1008);
#1010=ORIENTED_EDGE('',*,*,#344,.T.);
#1011=ORIENTED_EDGE('',*,*,#1000,.F.);
#1012=ORIENTED_EDGE('',*,*,#684,.F.);
#1013=DIRECTION('',(1.,0.,0.));
#1014=VECTOR('',#1013,1.);
#1015=CARTESIAN_POINT('',(0.5995,4.40697240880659,0.580188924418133));
#1016=LINE('',#1015,#1014);
#1017=EDGE_CURVE('E531',#675,#343,#1016,.T.);
#1018=ORIENTED_EDGE('',*,*,#1017,.T.);
#1019=EDGE_LOOP('',(#1010,#1011,#1012,#1018));
#1020=FACE_BOUND('',#1019,.T.);
#1021=ADVANCED_FACE('F818',(#1020),#1009,.F.);
#1022=CARTESIAN_POINT('',(0.5995,4.40697240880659,0.580188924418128));
#1023=DIRECTION('',(0.,-0.642592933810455,-0.766207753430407));
#1024=DIRECTION('',(0.,0.766207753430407,-0.642592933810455));
#1025=AXIS2_PLACEMENT_3D('',#1022,#1023,#1024);
#1026=PLANE('',#1025);
#1027=ORIENTED_EDGE('',*,*,#352,.T.);
#1028=ORIENTED_EDGE('',*,*,#1017,.F.);
#1029=ORIENTED_EDGE('',*,*,#676,.F.);
#1030=DIRECTION('',(1.,0.,0.));
#1031=VECTOR('',#1030,1.);
#1032=CARTESIAN_POINT('',(0.5995,3.86418626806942,1.03540558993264));
#1033=LINE('',#1032,#1031);
#1034=EDGE_CURVE('E519',#667,#351,#1033,.T.);
#1035=ORIENTED_EDGE('',*,*,#1034,.T.);
#1036=EDGE_LOOP('',(#1027,#1028,#1029,#1035));
#1037=FACE_BOUND('',#1036,.T.);
#1038=ADVANCED_FACE('F1039',(#1037),#1026,.F.);
#1039=CARTESIAN_POINT('',(0.5995,3.86418626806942,1.03540558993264));
#1040=DIRECTION('',(0.,-0.939605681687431,0.342258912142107));
#1041=DIRECTION('',(0.,-0.342258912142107,-0.939605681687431));
#1042=AXIS2_PLACEMENT_3D('',#1039,#1040,#1041);
#1043=PLANE('',#1042);
#1044=ORIENTED_EDGE('',*,*,#360,.T.);
#1045=ORIENTED_EDGE('',*,*,#1034,.F.);
#1046=ORIENTED_EDGE('',*,*,#668,.F.);
#1047=DIRECTION('',(1.,0.,0.));
#1048=VECTOR('',#1047,1.);
#1049=CARTESIAN_POINT('',(0.5995,4.10664452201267,1.70102785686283));
#1050=LINE('',#1049,#1048);
#1051=EDGE_CURVE('E515',#659,#359,#1050,.T.);
#1052=ORIENTED_EDGE('',*,*,#1051,.T.);
#1053=EDGE_LOOP('',(#1044,#1045,#1046,#1052));
#1054=FACE_BOUND('',#1053,.T.);
#1055=ADVANCED_FACE('F813',(#1054),#1043,.F.);
#1056=CARTESIAN_POINT('',(0.5995,2.70594455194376,3.52645559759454));
#1057=DIRECTION('',(0.,0.0874088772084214,-0.996172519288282));
#1058=DIRECTION('',(0.,0.996172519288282,0.0874088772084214));
#1059=AXIS2_PLACEMENT_3D('',#1056,#1057,#1058);
#1060=PLANE('',#1059);
#1061=ORIENTED_EDGE('',*,*,#400,.T.);
#1062=DIRECTION('',(1.,0.,0.));
#1063=VECTOR('',#1062,1.);
#1064=CARTESIAN_POINT('',(0.5995,2.70594455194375,3.52645559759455));
#1065=LINE('',#1064,#1063);
#1066=EDGE_CURVE('E620',#627,#391,#1065,.T.);
#1067=ORIENTED_EDGE('',*,*,#1066,.F.);
#1068=ORIENTED_EDGE('',*,*,#628,.F.);
#1069=DIRECTION('',(1.,0.,0.));
#1070=VECTOR('',#1069,1.);
#1071=CARTESIAN_POINT('',(0.5995,2.00024999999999,3.46453462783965));
#1072=LINE('',#1071,#1070);
#1073=EDGE_CURVE('E494',#619,#399,#1072,.T.);
#1074=ORIENTED_EDGE('',*,*,#1073,.T.);
#1075=EDGE_LOOP('',(#1061,#1067,#1068,#1074));
#1076=FACE_BOUND('',#1075,.T.);
#1077=ADVANCED_FACE('F793',(#1076),#1060,.F.);
#1078=CARTESIAN_POINT('',(0.5995,2.00024999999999,3.46453462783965));
#1079=DIRECTION('',(0.,-0.906415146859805,-0.422387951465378));
#1080=DIRECTION('',(0.,0.422387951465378,-0.906415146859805));
#1081=AXIS2_PLACEMENT_3D('',#1078,#1079,#1080);
#1082=PLANE('',#1081);
#1083=ORIENTED_EDGE('',*,*,#406,.T.);
#1084=ORIENTED_EDGE('',*,*,#1073,.F.);
#1085=ORIENTED_EDGE('',*,*,#620,.F.);
#1086=DIRECTION('',(1.,0.,0.));
#1087=VECTOR('',#1086,1.);
#1088=CARTESIAN_POINT('',(0.5995,1.70102785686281,4.10664452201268));
#1089=LINE('',#1088,#1087);
#1090=EDGE_CURVE('E484',#611,#31,#1089,.T.);
#1091=ORIENTED_EDGE('',*,*,#1090,.T.);
#1092=EDGE_LOOP('',(#1083,#1084,#1085,#1091));
#1093=FACE_BOUND('',#1092,.T.);
#1094=ADVANCED_FACE('F789',(#1093),#1082,.F.);
#1095=CARTESIAN_POINT('',(0.5995,3.52645559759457,-2.70594455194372));
#1096=DIRECTION('',(0.,-0.996172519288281,-0.0874088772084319));
#1097=DIRECTION('',(0.,0.0874088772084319,-0.996172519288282));
#1098=AXIS2_PLACEMENT_3D('',#1095,#1096,#1097);
#1099=PLANE('',#1098);
#1100=ORIENTED_EDGE('',*,*,#304,.T.);
#1101=DIRECTION('',(1.,0.,0.));
#1102=VECTOR('',#1101,1.);
#1103=CARTESIAN_POINT('',(0.5995,3.52645559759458,-2.70594455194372));
#1104=LINE('',#1103,#1102);
#1105=EDGE_CURVE('E766',#723,#295,#1104,.T.);
#1106=ORIENTED_EDGE('',*,*,#1105,.F.);
#1107=ORIENTED_EDGE('',*,*,#724,.F.);
#1108=DIRECTION('',(1.,0.,0.));
#1109=VECTOR('',#1108,1.);
#1110=CARTESIAN_POINT('',(0.5995,3.46453462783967,-2.00024999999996));
#1111=LINE('',#1110,#1109);
#1112=EDGE_CURVE('E477',#715,#303,#1111,.T.);
#1113=ORIENTED_EDGE('',*,*,#1112,.T.);
#1114=EDGE_LOOP('',(#1100,#1106,#1107,#1113));
#1115=FACE_BOUND('',#1114,.T.);
#1116=ADVANCED_FACE('F841',(#1115),#1099,.F.);
#1117=CARTESIAN_POINT('',(0.5995,3.46453462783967,-2.00024999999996));
#1118=DIRECTION('',(0.,-0.422387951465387,0.906415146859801));
#1119=DIRECTION('',(0.,-0.906415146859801,-0.422387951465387));
#1120=AXIS2_PLACEMENT_3D('',#1117,#1118,#1119);
#1121=PLANE('',#1120);
#1122=ORIENTED_EDGE('',*,*,#312,.T.);
#1123=ORIENTED_EDGE('',*,*,#1112,.F.);
#1124=ORIENTED_EDGE('',*,*,#716,.F.);
#1125=DIRECTION('',(1.,0.,0.));
#1126=VECTOR('',#1125,1.);
#1127=CARTESIAN_POINT('',(0.5995,4.10664452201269,-1.70102785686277));
#1128=LINE('',#1127,#1126);
#1129=EDGE_CURVE('E467',#707,#311,#1128,.T.);
#1130=ORIENTED_EDGE('',*,*,#1129,.T.);
#1131=EDGE_LOOP('',(#1122,#1123,#1124,#1130));
#1132=FACE_BOUND('',#1131,.T.);
#1133=ADVANCED_FACE('F835',(#1132),#1121,.F.);
#1134=CARTESIAN_POINT('',(0.5995,1.70102785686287,-4.10664452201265));
#1135=DIRECTION('',(0.,-0.906415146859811,0.422387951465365));
#1136=DIRECTION('',(0.,-0.422387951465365,-0.906415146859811));
#1137=AXIS2_PLACEMENT_3D('',#1134,#1135,#1136);
#1138=PLANE('',#1137);
#1139=ORIENTED_EDGE('',*,*,#272,.T.);
#1140=DIRECTION('',(1.,0.,0.));
#1141=VECTOR('',#1140,1.);
#1142=CARTESIAN_POINT('',(0.5995,1.70102785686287,-4.10664452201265));
#1143=LINE('',#1142,#1141);
#1144=EDGE_CURVE('E751',#755,#263,#1143,.T.);
#1145=ORIENTED_EDGE('',*,*,#1144,.F.);
#1146=ORIENTED_EDGE('',*,*,#756,.F.);
#1147=DIRECTION('',(1.,0.,0.));
#1148=VECTOR('',#1147,1.);
#1149=CARTESIAN_POINT('',(0.5995,2.00025000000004,-3.46453462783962));
#1150=LINE('',#1149,#1148);
#1151=EDGE_CURVE('E460',#747,#271,#1150,.T.);
#1152=ORIENTED_EDGE('',*,*,#1151,.T.);
#1153=EDGE_LOOP('',(#1139,#1145,#1146,#1152));
#1154=FACE_BOUND('',#1153,.T.);
#1155=ADVANCED_FACE('F858',(#1154),#1138,.F.);
#1156=CARTESIAN_POINT('',(0.5995,2.00025000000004,-3.46453462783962));
#1157=DIRECTION('',(0.,0.0874088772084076,0.996172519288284));
#1158=DIRECTION('',(0.,-0.996172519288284,0.0874088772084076));
#1159=AXIS2_PLACEMENT_3D('',#1156,#1157,#1158);
#1160=PLANE('',#1159);
#1161=ORIENTED_EDGE('',*,*,#280,.T.);
#1162=ORIENTED_EDGE('',*,*,#1151,.F.);
#1163=ORIENTED_EDGE('',*,*,#748,.F.);
#1164=DIRECTION('',(1.,0.,0.));
#1165=VECTOR('',#1164,1.);
#1166=CARTESIAN_POINT('',(0.5995,2.70594455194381,-3.52645559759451));
#1167=LINE('',#1166,#1165);
#1168=EDGE_CURVE('E450',#739,#279,#1167,.T.);
#1169=ORIENTED_EDGE('',*,*,#1168,.T.);
#1170=EDGE_LOOP('',(#1161,#1162,#1163,#1169));
#1171=FACE_BOUND('',#1170,.T.);
#1172=ADVANCED_FACE('F851',(#1171),#1160,.F.);
#1173=CARTESIAN_POINT('',(0.5995,-0.580188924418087,-4.40697240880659));
#1174=DIRECTION('',(0.,-0.573784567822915,0.819006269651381));
#1175=DIRECTION('',(0.,-0.819006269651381,-0.573784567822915));
#1176=AXIS2_PLACEMENT_3D('',#1173,#1174,#1175);
#1177=PLANE('',#1176);
#1178=ORIENTED_EDGE('',*,*,#240,.T.);
#1179=DIRECTION('',(1.,0.,0.));
#1180=VECTOR('',#1179,1.);
#1181=CARTESIAN_POINT('',(0.5995,-0.580188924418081,-4.40697240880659));
#1182=LINE('',#1181,#1180);
#1183=EDGE_CURVE('E736',#787,#231,#1182,.T.);
#1184=ORIENTED_EDGE('',*,*,#1183,.F.);
#1185=ORIENTED_EDGE('',*,*,#788,.F.);
#1186=DIRECTION('',(1.,0.,0.));
#1187=VECTOR('',#1186,1.);
#1188=CARTESIAN_POINT('',(0.5995,0.,-4.0005));
#1189=LINE('',#1188,#1187);
#1190=EDGE_CURVE('E443',#779,#239,#1189,.T.);
#1191=ORIENTED_EDGE('',*,*,#1190,.T.);
#1192=EDGE_LOOP('',(#1178,#1184,#1185,#1191));
#1193=FACE_BOUND('',#1192,.T.);
#1194=ADVANCED_FACE('F874',(#1193),#1177,.F.);
#1195=CARTESIAN_POINT('',(0.5995,0.,-4.0005));
#1196=DIRECTION('',(0.,0.573784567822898,0.819006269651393));
#1197=DIRECTION('',(0.,-0.819006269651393,0.573784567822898));
#1198=AXIS2_PLACEMENT_3D('',#1195,#1196,#1197);
#1199=PLANE('',#1198);
#1200=ORIENTED_EDGE('',*,*,#248,.T.);
#1201=ORIENTED_EDGE('',*,*,#1190,.F.);
#1202=ORIENTED_EDGE('',*,*,#780,.F.);
#1203=DIRECTION('',(1.,0.,0.));
#1204=VECTOR('',#1203,1.);
#1205=CARTESIAN_POINT('',(0.5995,0.58018892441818,-4.40697240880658));
#1206=LINE('',#1205,#1204);
#1207=EDGE_CURVE('E433',#771,#247,#1206,.T.);
#1208=ORIENTED_EDGE('',*,*,#1207,.T.);
#1209=EDGE_LOOP('',(#1200,#1201,#1202,#1208));
#1210=FACE_BOUND('',#1209,.T.);
#1211=ADVANCED_FACE('F867',(#1210),#1199,.F.);
#1212=CARTESIAN_POINT('',(0.5995,-2.70594455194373,-3.52645559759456));
#1213=DIRECTION('',(0.,-0.0874088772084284,0.996172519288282));
#1214=DIRECTION('',(0.,-0.996172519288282,-0.0874088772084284));
#1215=AXIS2_PLACEMENT_3D('',#1212,#1213,#1214);
#1216=PLANE('',#1215);
#1217=ORIENTED_EDGE('',*,*,#208,.T.);
#1218=DIRECTION('',(1.,0.,0.));
#1219=VECTOR('',#1218,1.);
#1220=CARTESIAN_POINT('',(0.5995,-2.70594455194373,-3.52645559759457));
#1221=LINE('',#1220,#1219);
#1222=EDGE_CURVE('E721',#819,#199,#1221,.T.);
#1223=ORIENTED_EDGE('',*,*,#1222,.F.);
#1224=ORIENTED_EDGE('',*,*,#820,.F.);
#1225=DIRECTION('',(1.,0.,0.));
#1226=VECTOR('',#1225,1.);
#1227=CARTESIAN_POINT('',(0.5995,-2.00024999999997,-3.46453462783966));
#1228=LINE('',#1227,#1226);
#1229=EDGE_CURVE('E426',#811,#207,#1228,.T.);
#1230=ORIENTED_EDGE('',*,*,#1229,.T.);
#1231=EDGE_LOOP('',(#1217,#1223,#1224,#1230));
#1232=FACE_BOUND('',#1231,.T.);
#1233=ADVANCED_FACE('F890',(#1232),#1216,.F.);
#1234=CARTESIAN_POINT('',(0.5995,-2.00024999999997,-3.46453462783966));
#1235=DIRECTION('',(0.,0.906415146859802,0.422387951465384));
#1236=DIRECTION('',(0.,-0.422387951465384,0.906415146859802));
#1237=AXIS2_PLACEMENT_3D('',#1234,#1235,#1236);
#1238=PLANE('',#1237);
#1239=ORIENTED_EDGE('',*,*,#216,.T.);
#1240=ORIENTED_EDGE('',*,*,#1229,.F.);
#1241=ORIENTED_EDGE('',*,*,#812,.F.);
#1242=DIRECTION('',(1.,0.,0.));
#1243=VECTOR('',#1242,1.);
#1244=CARTESIAN_POINT('',(0.5995,-1.70102785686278,-4.10664452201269));
#1245=LINE('',#1244,#1243);
#1246=EDGE_CURVE('E416',#803,#215,#1245,.T.);
#1247=ORIENTED_EDGE('',*,*,#1246,.T.);
#1248=EDGE_LOOP('',(#1239,#1240,#1241,#1247));
#1249=FACE_BOUND('',#1248,.T.);
#1250=ADVANCED_FACE('F883',(#1249),#1238,.F.);
#1251=CARTESIAN_POINT('',(0.5995,-4.10664452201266,-1.70102785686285));
#1252=DIRECTION('',(0.,0.422387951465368,0.906415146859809));
#1253=DIRECTION('',(0.,-0.906415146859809,0.422387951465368));
#1254=AXIS2_PLACEMENT_3D('',#1251,#1252,#1253);
#1255=PLANE('',#1254);
#1256=ORIENTED_EDGE('',*,*,#176,.T.);
#1257=DIRECTION('',(1.,0.,0.));
#1258=VECTOR('',#1257,1.);
#1259=CARTESIAN_POINT('',(0.5995,-4.10664452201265,-1.70102785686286));
#1260=LINE('',#1259,#1258);
#1261=EDGE_CURVE('E706',#851,#167,#1260,.T.);
#1262=ORIENTED_EDGE('',*,*,#1261,.F.);
#1263=ORIENTED_EDGE('',*,*,#852,.F.);
#1264=DIRECTION('',(1.,0.,0.));
#1265=VECTOR('',#1264,1.);
#1266=CARTESIAN_POINT('',(0.5995,-3.46453462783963,-2.00025000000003));
#1267=LINE('',#1266,#1265);
#1268=EDGE_CURVE('E409',#843,#175,#1267,.T.);
#1269=ORIENTED_EDGE('',*,*,#1268,.T.);
#1270=EDGE_LOOP('',(#1256,#1262,#1263,#1269));
#1271=FACE_BOUND('',#1270,.T.);
#1272=ADVANCED_FACE('F906',(#1271),#1255,.F.);
#1273=CARTESIAN_POINT('',(0.5995,-3.46453462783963,-2.00025000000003));
#1274=DIRECTION('',(0.,0.996172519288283,-0.087408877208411));
#1275=DIRECTION('',(0.,0.087408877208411,0.996172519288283));
#1276=AXIS2_PLACEMENT_3D('',#1273,#1274,#1275);
#1277=PLANE('',#1276);
#1278=ORIENTED_EDGE('',*,*,#184,.T.);
#1279=ORIENTED_EDGE('',*,*,#1268,.F.);
#1280=ORIENTED_EDGE('',*,*,#844,.F.);
#1281=DIRECTION('',(1.,0.,0.));
#1282=VECTOR('',#1281,1.);
#1283=CARTESIAN_POINT('',(0.5995,-3.52645559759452,-2.70594455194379));
#1284=LINE('',#1283,#1282);
#1285=EDGE_CURVE('E399',#835,#183,#1284,.T.);
#1286=ORIENTED_EDGE('',*,*,#1285,.T.);
#1287=EDGE_LOOP('',(#1278,#1279,#1280,#1286));
#1288=FACE_BOUND('',#1287,.T.);
#1289=ADVANCED_FACE('F899',(#1288),#1277,.F.);
#1290=CARTESIAN_POINT('',(0.5995,-4.40697240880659,0.580188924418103));
#1291=DIRECTION('',(0.,0.819006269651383,0.573784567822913));
#1292=DIRECTION('',(0.,-0.573784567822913,0.819006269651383));
#1293=AXIS2_PLACEMENT_3D('',#1290,#1291,#1292);
#1294=PLANE('',#1293);
#1295=ORIENTED_EDGE('',*,*,#144,.T.);
#1296=DIRECTION('',(1.,0.,0.));
#1297=VECTOR('',#1296,1.);
#1298=CARTESIAN_POINT('',(0.5995,-4.40697240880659,0.580188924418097));
#1299=LINE('',#1298,#1297);
#1300=EDGE_CURVE('E691',#883,#135,#1299,.T.);
#1301=ORIENTED_EDGE('',*,*,#1300,.F.);
#1302=ORIENTED_EDGE('',*,*,#884,.F.);
#1303=DIRECTION('',(1.,0.,0.));
#1304=VECTOR('',#1303,1.);
#1305=CARTESIAN_POINT('',(0.5995,-4.0005,0.));
#1306=LINE('',#1305,#1304);
#1307=EDGE_CURVE('E392',#875,#143,#1306,.T.);
#1308=ORIENTED_EDGE('',*,*,#1307,.T.);
#1309=EDGE_LOOP('',(#1295,#1301,#1302,#1308));
#1310=FACE_BOUND('',#1309,.T.);
#1311=ADVANCED_FACE('F922',(#1310),#1294,.F.);
#1312=CARTESIAN_POINT('',(0.5995,-4.0005,0.));
#1313=DIRECTION('',(0.,0.819006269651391,-0.573784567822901));
#1314=DIRECTION('',(0.,0.573784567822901,0.819006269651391));
#1315=AXIS2_PLACEMENT_3D('',#1312,#1313,#1314);
#1316=PLANE('',#1315);
#1317=ORIENTED_EDGE('',*,*,#152,.T.);
#1318=ORIENTED_EDGE('',*,*,#1307,.F.);
#1319=ORIENTED_EDGE('',*,*,#876,.F.);
#1320=DIRECTION('',(1.,0.,0.));
#1321=VECTOR('',#1320,1.);
#1322=CARTESIAN_POINT('',(0.5995,-4.40697240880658,-0.580188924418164));
#1323=LINE('',#1322,#1321);
#1324=EDGE_CURVE('E382',#867,#151,#1323,.T.);
#1325=ORIENTED_EDGE('',*,*,#1324,.T.);
#1326=EDGE_LOOP('',(#1317,#1318,#1319,#1325));
#1327=FACE_BOUND('',#1326,.T.);
#1328=ADVANCED_FACE('F915',(#1327),#1316,.F.);
#1329=CARTESIAN_POINT('',(0.5995,-3.52645559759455,2.70594455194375));
#1330=DIRECTION('',(0.,0.996172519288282,0.087408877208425));
#1331=DIRECTION('',(0.,-0.087408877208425,0.996172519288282));
#1332=AXIS2_PLACEMENT_3D('',#1329,#1330,#1331);
#1333=PLANE('',#1332);
#1334=ORIENTED_EDGE('',*,*,#112,.T.);
#1335=DIRECTION('',(1.,0.,0.));
#1336=VECTOR('',#1335,1.);
#1337=CARTESIAN_POINT('',(0.5995,-3.52645559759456,2.70594455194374));
#1338=LINE('',#1337,#1336);
#1339=EDGE_CURVE('E667',#915,#103,#1338,.T.);
#1340=ORIENTED_EDGE('',*,*,#1339,.F.);
#1341=ORIENTED_EDGE('',*,*,#916,.F.);
#1342=DIRECTION('',(1.,0.,0.));
#1343=VECTOR('',#1342,1.);
#1344=CARTESIAN_POINT('',(0.5995,-3.46453462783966,2.00024999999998));
#1345=LINE('',#1344,#1343);
#1346=EDGE_CURVE('E375',#907,#111,#1345,.T.);
#1347=ORIENTED_EDGE('',*,*,#1346,.T.);
#1348=EDGE_LOOP('',(#1334,#1340,#1341,#1347));
#1349=FACE_BOUND('',#1348,.T.);
#1350=ADVANCED_FACE('F937',(#1349),#1333,.F.);
#1351=CARTESIAN_POINT('',(0.5995,-3.46453462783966,2.00024999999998));
#1352=DIRECTION('',(0.,0.422387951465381,-0.906415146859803));
#1353=DIRECTION('',(0.,0.906415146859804,0.422387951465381));
#1354=AXIS2_PLACEMENT_3D('',#1351,#1352,#1353);
#1355=PLANE('',#1354);
#1356=ORIENTED_EDGE('',*,*,#120,.T.);
#1357=ORIENTED_EDGE('',*,*,#1346,.F.);
#1358=ORIENTED_EDGE('',*,*,#908,.F.);
#1359=DIRECTION('',(1.,0.,0.));
#1360=VECTOR('',#1359,1.);
#1361=CARTESIAN_POINT('',(0.5995,-4.10664452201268,1.7010278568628));
#1362=LINE('',#1361,#1360);
#1363=EDGE_CURVE('E371',#899,#119,#1362,.T.);
#1364=ORIENTED_EDGE('',*,*,#1363,.T.);
#1365=EDGE_LOOP('',(#1356,#1357,#1358,#1364));
#1366=FACE_BOUND('',#1365,.T.);
#1367=ADVANCED_FACE('F931',(#1366),#1355,.F.);
#1368=CARTESIAN_POINT('',(0.5995,-1.70102785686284,4.10664452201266));
#1369=DIRECTION('',(0.,0.906415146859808,-0.422387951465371));
#1370=DIRECTION('',(0.,0.422387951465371,0.906415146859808));
#1371=AXIS2_PLACEMENT_3D('',#1368,#1369,#1370);
#1372=PLANE('',#1371);
#1373=ORIENTED_EDGE('',*,*,#80,.T.);
#1374=DIRECTION('',(1.,0.,0.));
#1375=VECTOR('',#1374,1.);
#1376=CARTESIAN_POINT('',(0.5995,-1.70102785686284,4.10664452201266));
#1377=LINE('',#1376,#1375);
#1378=EDGE_CURVE('E340',#947,#71,#1377,.T.);
#1379=ORIENTED_EDGE('',*,*,#1378,.F.);
#1380=ORIENTED_EDGE('',*,*,#948,.F.);
#1381=DIRECTION('',(1.,0.,0.));
#1382=VECTOR('',#1381,1.);
#1383=CARTESIAN_POINT('',(0.5995,-2.00025000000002,3.46453462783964));
#1384=LINE('',#1383,#1382);
#1385=EDGE_CURVE('E362',#939,#79,#1384,.T.);
#1386=ORIENTED_EDGE('',*,*,#1385,.T.);
#1387=EDGE_LOOP('',(#1373,#1379,#1380,#1386));
#1388=FACE_BOUND('',#1387,.T.);
#1389=ADVANCED_FACE('F350',(#1388),#1372,.F.);
#1390=CARTESIAN_POINT('',(0.5995,-2.00025000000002,3.46453462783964));
#1391=DIRECTION('',(0.,-0.0874088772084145,-0.996172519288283));
#1392=DIRECTION('',(0.,0.996172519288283,-0.0874088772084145));
#1393=AXIS2_PLACEMENT_3D('',#1390,#1391,#1392);
#1394=PLANE('',#1393);
#1395=ORIENTED_EDGE('',*,*,#88,.T.);
#1396=ORIENTED_EDGE('',*,*,#1385,.F.);
#1397=ORIENTED_EDGE('',*,*,#940,.F.);
#1398=DIRECTION('',(1.,0.,0.));
#1399=VECTOR('',#1398,1.);
#1400=CARTESIAN_POINT('',(0.5995,-2.70594455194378,3.52645559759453));
#1401=LINE('',#1400,#1399);
#1402=EDGE_CURVE('E360',#931,#87,#1401,.T.);
#1403=ORIENTED_EDGE('',*,*,#1402,.T.);
#1404=EDGE_LOOP('',(#1395,#1396,#1397,#1403));
#1405=FACE_BOUND('',#1404,.T.);
#1406=ADVANCED_FACE('F659',(#1405),#1394,.F.);
#1407=CARTESIAN_POINT('',(0.5995,0.580188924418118,4.40697240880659));
#1408=DIRECTION('',(0.,0.57378456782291,-0.819006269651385));
#1409=DIRECTION('',(0.,0.819006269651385,0.57378456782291));
#1410=AXIS2_PLACEMENT_3D('',#1407,#1408,#1409);
#1411=PLANE('',#1410);
#1412=ORIENTED_EDGE('',*,*,#48,.T.);
#1413=DIRECTION('',(1.,0.,0.));
#1414=VECTOR('',#1413,1.);
#1415=CARTESIAN_POINT('',(0.5995,0.580188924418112,4.40697240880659));
#1416=LINE('',#1415,#1414);
#1417=EDGE_CURVE('E611',#601,#39,#1416,.T.);
#1418=ORIENTED_EDGE('',*,*,#1417,.F.);
#1419=ORIENTED_EDGE('',*,*,#978,.F.);
#1420=DIRECTION('',(1.,0.,0.));
#1421=VECTOR('',#1420,1.);
#1422=CARTESIAN_POINT('',(0.5995,0.,4.0005));
#1423=LINE('',#1422,#1421);
#1424=EDGE_CURVE('E646',#971,#47,#1423,.T.);
#1425=ORIENTED_EDGE('',*,*,#1424,.T.);
#1426=EDGE_LOOP('',(#1412,#1418,#1419,#1425));
#1427=FACE_BOUND('',#1426,.T.);
#1428=ADVANCED_FACE('F999',(#1427),#1411,.F.);
#1429=CARTESIAN_POINT('',(0.5995,0.,4.0005));
#1430=DIRECTION('',(0.,-0.573784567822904,-0.819006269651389));
#1431=DIRECTION('',(0.,0.819006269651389,-0.573784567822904));
#1432=AXIS2_PLACEMENT_3D('',#1429,#1430,#1431);
#1433=PLANE('',#1432);
#1434=ORIENTED_EDGE('',*,*,#56,.T.);
#1435=ORIENTED_EDGE('',*,*,#1424,.F.);
#1436=ORIENTED_EDGE('',*,*,#972,.F.);
#1437=DIRECTION('',(1.,0.,0.));
#1438=VECTOR('',#1437,1.);
#1439=CARTESIAN_POINT('',(0.5995,-0.580188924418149,4.40697240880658));
#1440=LINE('',#1439,#1438);
#1441=EDGE_CURVE('E637',#963,#55,#1440,.T.);
#1442=ORIENTED_EDGE('',*,*,#1441,.T.);
#1443=EDGE_LOOP('',(#1434,#1435,#1436,#1442));
#1444=FACE_BOUND('',#1443,.T.);
#1445=ADVANCED_FACE('F996',(#1444),#1433,.F.);
#1446=CARTESIAN_POINT('',(0.5995,4.10664452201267,1.70102785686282));
#1447=DIRECTION('',(0.,-0.422387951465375,-0.906415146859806));
#1448=DIRECTION('',(0.,0.906415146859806,-0.422387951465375));
#1449=AXIS2_PLACEMENT_3D('',#1446,#1447,#1448);
#1450=PLANE('',#1449);
#1451=ORIENTED_EDGE('',*,*,#368,.T.);
#1452=ORIENTED_EDGE('',*,*,#1051,.F.);
#1453=ORIENTED_EDGE('',*,*,#660,.F.);
#1454=DIRECTION('',(1.,0.,0.));
#1455=VECTOR('',#1454,1.);
#1456=CARTESIAN_POINT('',(0.5995,3.46453462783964,2.00025));
#1457=LINE('',#1456,#1455);
#1458=EDGE_CURVE('E631',#651,#367,#1457,.T.);
#1459=ORIENTED_EDGE('',*,*,#1458,.T.);
#1460=EDGE_LOOP('',(#1451,#1452,#1453,#1459));
#1461=FACE_BOUND('',#1460,.T.);
#1462=ADVANCED_FACE('F809',(#1461),#1450,.F.);
#1463=CARTESIAN_POINT('',(0.5995,3.46453462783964,2.00025));
#1464=DIRECTION('',(0.,-0.996172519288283,0.087408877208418));
#1465=DIRECTION('',(0.,-0.087408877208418,-0.996172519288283));
#1466=AXIS2_PLACEMENT_3D('',#1463,#1464,#1465);
#1467=PLANE('',#1466);
#1468=ORIENTED_EDGE('',*,*,#376,.T.);
#1469=ORIENTED_EDGE('',*,*,#1458,.F.);
#1470=ORIENTED_EDGE('',*,*,#652,.F.);
#1471=DIRECTION('',(1.,0.,0.));
#1472=VECTOR('',#1471,1.);
#1473=CARTESIAN_POINT('',(0.5995,3.52645559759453,2.70594455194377));
#1474=LINE('',#1473,#1472);
#1475=EDGE_CURVE('E626',#643,#375,#1474,.T.);
#1476=ORIENTED_EDGE('',*,*,#1475,.T.);
#1477=EDGE_LOOP('',(#1468,#1469,#1470,#1476));
#1478=FACE_BOUND('',#1477,.T.);
#1479=ADVANCED_FACE('F804',(#1478),#1467,.F.);
#1480=CARTESIAN_POINT('',(0.5995,3.52645559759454,2.70594455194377));
#1481=DIRECTION('',(0.,-0.173397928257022,-0.984851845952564));
#1482=DIRECTION('',(0.,0.984851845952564,-0.173397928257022));
#1483=AXIS2_PLACEMENT_3D('',#1480,#1481,#1482);
#1484=PLANE('',#1483);
#1485=ORIENTED_EDGE('',*,*,#384,.T.);
#1486=ORIENTED_EDGE('',*,*,#1475,.F.);
#1487=ORIENTED_EDGE('',*,*,#644,.F.);
#1488=DIRECTION('',(1.,0.,0.));
#1489=VECTOR('',#1488,1.);
#1490=CARTESIAN_POINT('',(0.5995,2.82878067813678,2.82878067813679));
#1491=LINE('',#1490,#1489);
#1492=EDGE_CURVE('E624',#635,#383,#1491,.T.);
#1493=ORIENTED_EDGE('',*,*,#1492,.T.);
#1494=EDGE_LOOP('',(#1485,#1486,#1487,#1493));
#1495=FACE_BOUND('',#1494,.T.);
#1496=ADVANCED_FACE('F801',(#1495),#1484,.F.);
#1497=CARTESIAN_POINT('',(0.5995,2.82878067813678,2.82878067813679));
#1498=DIRECTION('',(0.,-0.984851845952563,-0.173397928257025));
#1499=DIRECTION('',(0.,0.173397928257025,-0.984851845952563));
#1500=AXIS2_PLACEMENT_3D('',#1497,#1498,#1499);
#1501=PLANE('',#1500);
#1502=ORIENTED_EDGE('',*,*,#392,.T.);
#1503=ORIENTED_EDGE('',*,*,#1492,.F.);
#1504=ORIENTED_EDGE('',*,*,#636,.F.);
#1505=ORIENTED_EDGE('',*,*,#1066,.T.);
#1506=EDGE_LOOP('',(#1502,#1503,#1504,#1505));
#1507=FACE_BOUND('',#1506,.T.);
#1508=ADVANCED_FACE('F797',(#1507),#1501,.F.);
#1509=CARTESIAN_POINT('',(0.5995,-0.580188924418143,4.40697240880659));
#1510=DIRECTION('',(0.,0.766207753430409,-0.642592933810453));
#1511=DIRECTION('',(0.,0.642592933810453,0.766207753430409));
#1512=AXIS2_PLACEMENT_3D('',#1509,#1510,#1511);
#1513=PLANE('',#1512);
#1514=ORIENTED_EDGE('',*,*,#64,.T.);
#1515=ORIENTED_EDGE('',*,*,#1441,.F.);
#1516=ORIENTED_EDGE('',*,*,#964,.F.);
#1517=DIRECTION('',(1.,0.,0.));
#1518=VECTOR('',#1517,1.);
#1519=CARTESIAN_POINT('',(0.5995,-1.03540558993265,3.86418626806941));
#1520=LINE('',#1519,#1518);
#1521=EDGE_CURVE('E342',#955,#63,#1520,.T.);
#1522=ORIENTED_EDGE('',*,*,#1521,.T.);
#1523=EDGE_LOOP('',(#1514,#1515,#1516,#1522));
#1524=FACE_BOUND('',#1523,.T.);
#1525=ADVANCED_FACE('F991',(#1524),#1513,.F.);
#1526=CARTESIAN_POINT('',(0.5995,-1.03540558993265,3.86418626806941));
#1527=DIRECTION('',(0.,-0.342258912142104,-0.939605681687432));
#1528=DIRECTION('',(0.,0.939605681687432,-0.342258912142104));
#1529=AXIS2_PLACEMENT_3D('',#1526,#1527,#1528);
#1530=PLANE('',#1529);
#1531=ORIENTED_EDGE('',*,*,#72,.T.);
#1532=ORIENTED_EDGE('',*,*,#1521,.F.);
#1533=ORIENTED_EDGE('',*,*,#956,.F.);
#1534=ORIENTED_EDGE('',*,*,#1378,.T.);
#1535=EDGE_LOOP('',(#1531,#1532,#1533,#1534));
#1536=FACE_BOUND('',#1535,.T.);
#1537=ADVANCED_FACE('F339',(#1536),#1530,.F.);
#1538=CARTESIAN_POINT('',(0.5995,1.70102785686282,4.10664452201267));
#1539=DIRECTION('',(0.,0.34225891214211,-0.93960568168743));
#1540=DIRECTION('',(0.,0.93960568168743,0.34225891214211));
#1541=AXIS2_PLACEMENT_3D('',#1538,#1539,#1540);
#1542=PLANE('',#1541);
#1543=ORIENTED_EDGE('',*,*,#32,.T.);
#1544=ORIENTED_EDGE('',*,*,#1090,.F.);
#1545=ORIENTED_EDGE('',*,*,#612,.F.);
#1546=DIRECTION('',(1.,0.,0.));
#1547=VECTOR('',#1546,1.);
#1548=CARTESIAN_POINT('',(0.5995,1.03540558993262,3.86418626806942));
#1549=LINE('',#1548,#1547);
#1550=EDGE_CURVE('E608',#603,#29,#1549,.T.);
#1551=ORIENTED_EDGE('',*,*,#1550,.T.);
#1552=EDGE_LOOP('',(#1543,#1544,#1545,#1551));
#1553=FACE_BOUND('',#1552,.T.);
#1554=ADVANCED_FACE('F951',(#1553),#1542,.F.);
#1555=CARTESIAN_POINT('',(0.5995,1.03540558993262,3.86418626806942));
#1556=DIRECTION('',(0.,-0.766207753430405,-0.642592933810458));
#1557=DIRECTION('',(0.,0.642592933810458,-0.766207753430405));
#1558=AXIS2_PLACEMENT_3D('',#1555,#1556,#1557);
#1559=PLANE('',#1558);
#1560=ORIENTED_EDGE('',*,*,#40,.T.);
#1561=ORIENTED_EDGE('',*,*,#1550,.F.);
#1562=ORIENTED_EDGE('',*,*,#604,.F.);
#1563=ORIENTED_EDGE('',*,*,#1417,.T.);
#1564=EDGE_LOOP('',(#1560,#1561,#1562,#1563));
#1565=FACE_BOUND('',#1564,.T.);
#1566=ADVANCED_FACE('F944',(#1565),#1559,.F.);
#1567=CARTESIAN_POINT('',(0.5995,-2.70594455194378,3.52645559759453));
#1568=DIRECTION('',(0.,0.984851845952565,-0.173397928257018));
#1569=DIRECTION('',(0.,0.173397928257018,0.984851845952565));
#1570=AXIS2_PLACEMENT_3D('',#1567,#1568,#1569);
#1571=PLANE('',#1570);
#1572=ORIENTED_EDGE('',*,*,#96,.T.);
#1573=ORIENTED_EDGE('',*,*,#1402,.F.);
#1574=ORIENTED_EDGE('',*,*,#932,.F.);
#1575=DIRECTION('',(1.,0.,0.));
#1576=VECTOR('',#1575,1.);
#1577=CARTESIAN_POINT('',(0.5995,-2.8287806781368,2.82878067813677));
#1578=LINE('',#1577,#1576);
#1579=EDGE_CURVE('E664',#923,#95,#1578,.T.);
#1580=ORIENTED_EDGE('',*,*,#1579,.T.);
#1581=EDGE_LOOP('',(#1572,#1573,#1574,#1580));
#1582=FACE_BOUND('',#1581,.T.);
#1583=ADVANCED_FACE('F942',(#1582),#1571,.F.);
#1584=CARTESIAN_POINT('',(0.5995,-2.8287806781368,2.82878067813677));
#1585=DIRECTION('',(0.,0.173397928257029,-0.984851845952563));
#1586=DIRECTION('',(0.,0.984851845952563,0.173397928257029));
#1587=AXIS2_PLACEMENT_3D('',#1584,#1585,#1586);
#1588=PLANE('',#1587);
#1589=ORIENTED_EDGE('',*,*,#104,.T.);
#1590=ORIENTED_EDGE('',*,*,#1579,.F.);
#1591=ORIENTED_EDGE('',*,*,#924,.F.);
#1592=ORIENTED_EDGE('',*,*,#1339,.T.);
#1593=EDGE_LOOP('',(#1589,#1590,#1591,#1592));
#1594=FACE_BOUND('',#1593,.T.);
#1595=ADVANCED_FACE('F940',(#1594),#1588,.F.);
#1596=CARTESIAN_POINT('',(0.5995,-4.10664452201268,1.7010278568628));
#1597=DIRECTION('',(0.,0.939605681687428,0.342258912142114));
#1598=DIRECTION('',(0.,-0.342258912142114,0.939605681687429));
#1599=AXIS2_PLACEMENT_3D('',#1596,#1597,#1598);
#1600=PLANE('',#1599);
#1601=ORIENTED_EDGE('',*,*,#128,.T.);
#1602=ORIENTED_EDGE('',*,*,#1363,.F.);
#1603=ORIENTED_EDGE('',*,*,#900,.F.);
#1604=DIRECTION('',(1.,0.,0.));
#1605=VECTOR('',#1604,1.);
#1606=CARTESIAN_POINT('',(0.5995,-3.86418626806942,1.03540558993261));
#1607=LINE('',#1606,#1605);
#1608=EDGE_CURVE('E681',#891,#127,#1607,.T.);
#1609=ORIENTED_EDGE('',*,*,#1608,.T.);
#1610=EDGE_LOOP('',(#1601,#1602,#1603,#1609));
#1611=FACE_BOUND('',#1610,.T.);
#1612=ADVANCED_FACE('F928',(#1611),#1600,.F.);
#1613=CARTESIAN_POINT('',(0.5995,-3.86418626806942,1.03540558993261));
#1614=DIRECTION('',(0.,0.642592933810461,-0.766207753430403));
#1615=DIRECTION('',(0.,0.766207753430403,0.642592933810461));
#1616=AXIS2_PLACEMENT_3D('',#1613,#1614,#1615);
#1617=PLANE('',#1616);
#1618=ORIENTED_EDGE('',*,*,#136,.T.);
#1619=ORIENTED_EDGE('',*,*,#1608,.F.);
#1620=ORIENTED_EDGE('',*,*,#892,.F.);
#1621=ORIENTED_EDGE('',*,*,#1300,.T.);
#1622=EDGE_LOOP('',(#1618,#1619,#1620,#1621));
#1623=FACE_BOUND('',#1622,.T.);
#1624=ADVANCED_FACE('F926',(#1623),#1617,.F.);
#1625=CARTESIAN_POINT('',(0.5995,-4.40697240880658,-0.580188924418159));
#1626=DIRECTION('',(0.,0.64259293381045,0.766207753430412));
#1627=DIRECTION('',(0.,-0.766207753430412,0.64259293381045));
#1628=AXIS2_PLACEMENT_3D('',#1625,#1626,#1627);
#1629=PLANE('',#1628);
#1630=ORIENTED_EDGE('',*,*,#160,.T.);
#1631=ORIENTED_EDGE('',*,*,#1324,.F.);
#1632=ORIENTED_EDGE('',*,*,#868,.F.);
#1633=DIRECTION('',(1.,0.,0.));
#1634=VECTOR('',#1633,1.);
#1635=CARTESIAN_POINT('',(0.5995,-3.86418626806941,-1.03540558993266));
#1636=LINE('',#1635,#1634);
#1637=EDGE_CURVE('E695',#859,#159,#1636,.T.);
#1638=ORIENTED_EDGE('',*,*,#1637,.T.);
#1639=EDGE_LOOP('',(#1630,#1631,#1632,#1638));
#1640=FACE_BOUND('',#1639,.T.);
#1641=ADVANCED_FACE('F912',(#1640),#1629,.F.);
#1642=CARTESIAN_POINT('',(0.5995,-3.86418626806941,-1.03540558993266));
#1643=DIRECTION('',(0.,0.939605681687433,-0.342258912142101));
#1644=DIRECTION('',(0.,0.342258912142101,0.939605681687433));
#1645=AXIS2_PLACEMENT_3D('',#1642,#1643,#1644);
#1646=PLANE('',#1645);
#1647=ORIENTED_EDGE('',*,*,#168,.T.);
#1648=ORIENTED_EDGE('',*,*,#1637,.F.);
#1649=ORIENTED_EDGE('',*,*,#860,.F.);
#1650=ORIENTED_EDGE('',*,*,#1261,.T.);
#1651=EDGE_LOOP('',(#1647,#1648,#1649,#1650));
#1652=FACE_BOUND('',#1651,.T.);
#1653=ADVANCED_FACE('F910',(#1652),#1646,.F.);
#1654=CARTESIAN_POINT('',(0.5995,-3.52645559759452,-2.70594455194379));
#1655=DIRECTION('',(0.,0.173397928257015,0.984851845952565));
#1656=DIRECTION('',(0.,-0.984851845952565,0.173397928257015));
#1657=AXIS2_PLACEMENT_3D('',#1654,#1655,#1656);
#1658=PLANE('',#1657);
#1659=ORIENTED_EDGE('',*,*,#192,.T.);
#1660=ORIENTED_EDGE('',*,*,#1285,.F.);
#1661=ORIENTED_EDGE('',*,*,#836,.F.);
#1662=DIRECTION('',(1.,0.,0.));
#1663=VECTOR('',#1662,1.);
#1664=CARTESIAN_POINT('',(0.5995,-2.82878067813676,-2.82878067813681));
#1665=LINE('',#1664,#1663);
#1666=EDGE_CURVE('E710',#827,#191,#1665,.T.);
#1667=ORIENTED_EDGE('',*,*,#1666,.T.);
#1668=EDGE_LOOP('',(#1659,#1660,#1661,#1667));
#1669=FACE_BOUND('',#1668,.T.);
#1670=ADVANCED_FACE('F896',(#1669),#1658,.F.);
#1671=CARTESIAN_POINT('',(0.5995,-2.82878067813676,-2.82878067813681));
#1672=DIRECTION('',(0.,0.984851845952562,0.173397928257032));
#1673=DIRECTION('',(0.,-0.173397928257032,0.984851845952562));
#1674=AXIS2_PLACEMENT_3D('',#1671,#1672,#1673);
#1675=PLANE('',#1674);
#1676=ORIENTED_EDGE('',*,*,#200,.T.);
#1677=ORIENTED_EDGE('',*,*,#1666,.F.);
#1678=ORIENTED_EDGE('',*,*,#828,.F.);
#1679=ORIENTED_EDGE('',*,*,#1222,.T.);
#1680=EDGE_LOOP('',(#1676,#1677,#1678,#1679));
#1681=FACE_BOUND('',#1680,.T.);
#1682=ADVANCED_FACE('F894',(#1681),#1675,.F.);
#1683=CARTESIAN_POINT('',(0.5995,-1.70102785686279,-4.10664452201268));
#1684=DIRECTION('',(0.,-0.342258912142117,0.939605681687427));
#1685=DIRECTION('',(0.,-0.939605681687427,-0.342258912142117));
#1686=AXIS2_PLACEMENT_3D('',#1683,#1684,#1685);
#1687=PLANE('',#1686);
#1688=ORIENTED_EDGE('',*,*,#224,.T.);
#1689=ORIENTED_EDGE('',*,*,#1246,.F.);
#1690=ORIENTED_EDGE('',*,*,#804,.F.);
#1691=DIRECTION('',(1.,0.,0.));
#1692=VECTOR('',#1691,1.);
#1693=CARTESIAN_POINT('',(0.5995,-1.0354055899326,-3.86418626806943));
#1694=LINE('',#1693,#1692);
#1695=EDGE_CURVE('E725',#795,#223,#1694,.T.);
#1696=ORIENTED_EDGE('',*,*,#1695,.T.);
#1697=EDGE_LOOP('',(#1688,#1689,#1690,#1696));
#1698=FACE_BOUND('',#1697,.T.);
#1699=ADVANCED_FACE('F880',(#1698),#1687,.F.);
#1700=CARTESIAN_POINT('',(0.5995,-1.0354055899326,-3.86418626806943));
#1701=DIRECTION('',(0.,0.7662077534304,0.642592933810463));
#1702=DIRECTION('',(0.,-0.642592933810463,0.7662077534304));
#1703=AXIS2_PLACEMENT_3D('',#1700,#1701,#1702);
#1704=PLANE('',#1703);
#1705=ORIENTED_EDGE('',*,*,#232,.T.);
#1706=ORIENTED_EDGE('',*,*,#1695,.F.);
#1707=ORIENTED_EDGE('',*,*,#796,.F.);
#1708=ORIENTED_EDGE('',*,*,#1183,.T.);
#1709=EDGE_LOOP('',(#1705,#1706,#1707,#1708));
#1710=FACE_BOUND('',#1709,.T.);
#1711=ADVANCED_FACE('F878',(#1710),#1704,.F.);
#1712=CARTESIAN_POINT('',(0.5995,0.580188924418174,-4.40697240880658));
#1713=DIRECTION('',(0.,-0.766207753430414,0.642592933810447));
#1714=DIRECTION('',(0.,-0.642592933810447,-0.766207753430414));
#1715=AXIS2_PLACEMENT_3D('',#1712,#1713,#1714);
#1716=PLANE('',#1715);
#1717=ORIENTED_EDGE('',*,*,#256,.T.);
#1718=ORIENTED_EDGE('',*,*,#1207,.F.);
#1719=ORIENTED_EDGE('',*,*,#772,.F.);
#1720=DIRECTION('',(1.,0.,0.));
#1721=VECTOR('',#1720,1.);
#1722=CARTESIAN_POINT('',(0.5995,1.03540558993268,-3.86418626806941));
#1723=LINE('',#1722,#1721);
#1724=EDGE_CURVE('E740',#763,#255,#1723,.T.);
#1725=ORIENTED_EDGE('',*,*,#1724,.T.);
#1726=EDGE_LOOP('',(#1717,#1718,#1719,#1725));
#1727=FACE_BOUND('',#1726,.T.);
#1728=ADVANCED_FACE('F864',(#1727),#1716,.F.);
#1729=CARTESIAN_POINT('',(0.5995,1.03540558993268,-3.86418626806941));
#1730=DIRECTION('',(0.,0.342258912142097,0.939605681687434));
#1731=DIRECTION('',(0.,-0.939605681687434,0.342258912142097));
#1732=AXIS2_PLACEMENT_3D('',#1729,#1730,#1731);
#1733=PLANE('',#1732);
#1734=ORIENTED_EDGE('',*,*,#264,.T.);
#1735=ORIENTED_EDGE('',*,*,#1724,.F.);
#1736=ORIENTED_EDGE('',*,*,#764,.F.);
#1737=ORIENTED_EDGE('',*,*,#1144,.T.);
#1738=EDGE_LOOP('',(#1734,#1735,#1736,#1737));
#1739=FACE_BOUND('',#1738,.T.);
#1740=ADVANCED_FACE('F862',(#1739),#1733,.F.);
#1741=CARTESIAN_POINT('',(0.5995,2.7059445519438,-3.52645559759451));
#1742=DIRECTION('',(0.,-0.984851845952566,0.173397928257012));
#1743=DIRECTION('',(0.,-0.173397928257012,-0.984851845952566));
#1744=AXIS2_PLACEMENT_3D('',#1741,#1742,#1743);
#1745=PLANE('',#1744);
#1746=ORIENTED_EDGE('',*,*,#288,.T.);
#1747=ORIENTED_EDGE('',*,*,#1168,.F.);
#1748=ORIENTED_EDGE('',*,*,#740,.F.);
#1749=DIRECTION('',(1.,0.,0.));
#1750=VECTOR('',#1749,1.);
#1751=CARTESIAN_POINT('',(0.5995,2.82878067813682,-2.82878067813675));
#1752=LINE('',#1751,#1750);
#1753=EDGE_CURVE('E755',#731,#287,#1752,.T.);
#1754=ORIENTED_EDGE('',*,*,#1753,.T.);
#1755=EDGE_LOOP('',(#1746,#1747,#1748,#1754));
#1756=FACE_BOUND('',#1755,.T.);
#1757=ADVANCED_FACE('F848',(#1756),#1745,.F.);
#1758=CARTESIAN_POINT('',(0.5995,2.82878067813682,-2.82878067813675));
#1759=DIRECTION('',(0.,-0.173397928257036,0.984851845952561));
#1760=DIRECTION('',(0.,-0.984851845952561,-0.173397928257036));
#1761=AXIS2_PLACEMENT_3D('',#1758,#1759,#1760);
#1762=PLANE('',#1761);
#1763=ORIENTED_EDGE('',*,*,#296,.T.);
#1764=ORIENTED_EDGE('',*,*,#1753,.F.);
#1765=ORIENTED_EDGE('',*,*,#732,.F.);
#1766=ORIENTED_EDGE('',*,*,#1105,.T.);
#1767=EDGE_LOOP('',(#1763,#1764,#1765,#1766));
#1768=FACE_BOUND('',#1767,.T.);
#1769=ADVANCED_FACE('F846',(#1768),#1762,.F.);
#1770=CARTESIAN_POINT('',(0.5995,4.10664452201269,-1.70102785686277));
#1771=DIRECTION('',(0.,-0.939605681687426,-0.34225891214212));
#1772=DIRECTION('',(0.,0.34225891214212,-0.939605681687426));
#1773=AXIS2_PLACEMENT_3D('',#1770,#1771,#1772);
#1774=PLANE('',#1773);
#1775=ORIENTED_EDGE('',*,*,#320,.T.);
#1776=ORIENTED_EDGE('',*,*,#1129,.F.);
#1777=ORIENTED_EDGE('',*,*,#708,.F.);
#1778=DIRECTION('',(1.,0.,0.));
#1779=VECTOR('',#1778,1.);
#1780=CARTESIAN_POINT('',(0.5995,3.86418626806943,-1.03540558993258));
#1781=LINE('',#1780,#1779);
#1782=EDGE_CURVE('E770',#699,#319,#1781,.T.);
#1783=ORIENTED_EDGE('',*,*,#1782,.T.);
#1784=EDGE_LOOP('',(#1775,#1776,#1777,#1783));
#1785=FACE_BOUND('',#1784,.T.);
#1786=ADVANCED_FACE('F832',(#1785),#1774,.F.);
#1787=CARTESIAN_POINT('',(0.5995,3.86418626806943,-1.03540558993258));
#1788=DIRECTION('',(0.,-0.642592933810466,0.766207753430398));
#1789=DIRECTION('',(0.,-0.766207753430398,-0.642592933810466));
#1790=AXIS2_PLACEMENT_3D('',#1787,#1788,#1789);
#1791=PLANE('',#1790);
#1792=ORIENTED_EDGE('',*,*,#328,.T.);
#1793=ORIENTED_EDGE('',*,*,#1782,.F.);
#1794=ORIENTED_EDGE('',*,*,#700,.F.);
#1795=ORIENTED_EDGE('',*,*,#993,.T.);
#1796=EDGE_LOOP('',(#1792,#1793,#1794,#1795));
#1797=FACE_BOUND('',#1796,.T.);
#1798=ADVANCED_FACE('F828',(#1797),#1791,.F.);
#1799=CLOSED_SHELL('',(#421,#441,#461,#470,#487,#507,#527,#547,#567,#587,#982,#1004,#1021,#1038,
#1055,#1077,#1094,#1116,#1133,#1155,#1172,#1194,#1211,#1233,#1250,#1272,#1289,#1311,#1328,#1350,
#1367,#1389,#1406,#1428,#1445,#1462,#1479,#1496,#1508,#1525,#1537,#1554,#1566,#1583,#1595,#1612,
#1624,#1641,#1653,#1670,#1682,#1699,#1711,#1728,#1740,#1757,#1769,#1786,#1798));
#1800=MANIFOLD_SOLID_BREP('B2',#1799);
#1801=ADVANCED_BREP_SHAPE_REPRESENTATION('',(#18,#1800),#14);
#1802=SHAPE_DEFINITION_REPRESENTATION(#9,#1801);
ENDSEC;
END-ISO-10303-21;
